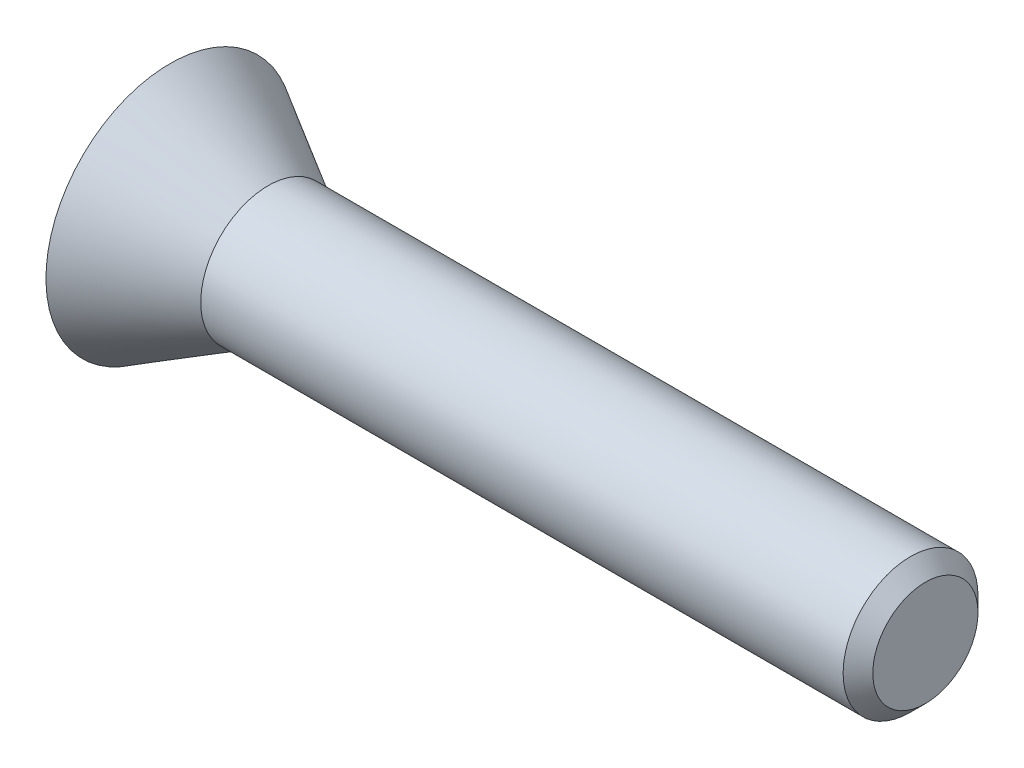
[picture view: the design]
ISO-10303-21;
HEADER;
FILE_DESCRIPTION(('STEP AP214'),'2;1');
FILE_NAME('part.step','',(''),(''),'','','');
FILE_SCHEMA(('AUTOMOTIVE_DESIGN { 1 0 10303 214 1 1 1 1 }'));
ENDSEC;
DATA;
#1=APPLICATION_CONTEXT('core data for automotive mechanical design processes');
#2=APPLICATION_PROTOCOL_DEFINITION('international standard','automotive_design',2000,#1);
#3=PRODUCT_CONTEXT('',#1,'mechanical');
#4=PRODUCT('Part','Part','',(#3));
#5=PRODUCT_RELATED_PRODUCT_CATEGORY('part','',(#4));
#6=PRODUCT_DEFINITION_FORMATION('','',#4);
#7=PRODUCT_DEFINITION_CONTEXT('part definition',#1,'design');
#8=PRODUCT_DEFINITION('design','',#6,#7);
#9=PRODUCT_DEFINITION_SHAPE('','',#8);
#10=(LENGTH_UNIT() NAMED_UNIT(*) SI_UNIT(.MILLI.,.METRE.));
#11=(NAMED_UNIT(*) PLANE_ANGLE_UNIT() SI_UNIT($,.RADIAN.));
#12=(NAMED_UNIT(*) SI_UNIT($,.STERADIAN.) SOLID_ANGLE_UNIT());
#13=UNCERTAINTY_MEASURE_WITH_UNIT(LENGTH_MEASURE(1.E-05),#10,'distance_accuracy_value','');
#14=(GEOMETRIC_REPRESENTATION_CONTEXT(3) GLOBAL_UNCERTAINTY_ASSIGNED_CONTEXT((#13)) GLOBAL_UNIT_ASSIGNED_CONTEXT((#10,
#11,#12)) REPRESENTATION_CONTEXT('',''));
#15=CARTESIAN_POINT('',(0.,0.,0.));
#16=DIRECTION('',(0.,0.,1.));
#17=DIRECTION('',(1.,0.,0.));
#18=AXIS2_PLACEMENT_3D('',#15,#16,#17);
#19=CARTESIAN_POINT('',(-7.,0.,0.));
#20=DIRECTION('',(1.,0.,0.));
#21=DIRECTION('',(0.,0.,-1.));
#22=AXIS2_PLACEMENT_3D('',#19,#20,#21);
#23=PLANE('',#22);
#24=CARTESIAN_POINT('',(-7.,-1.00253926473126,-0.988193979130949));
#25=CARTESIAN_POINT('',(-7.,-1.00211098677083,-0.966842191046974));
#26=CARTESIAN_POINT('',(-7.,-1.00127782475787,-0.92530491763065));
#27=CARTESIAN_POINT('',(-7.,-0.994369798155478,-0.864879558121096));
#28=CARTESIAN_POINT('',(-7.,-0.982370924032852,-0.808239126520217));
#29=CARTESIAN_POINT('',(-7.,-0.965811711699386,-0.755134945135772));
#30=CARTESIAN_POINT('',(-7.,-0.944644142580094,-0.70556513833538));
#31=CARTESIAN_POINT('',(-7.,-0.918692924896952,-0.659749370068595));
#32=CARTESIAN_POINT('',(-7.,-0.887939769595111,-0.617664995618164));
#33=CARTESIAN_POINT('',(-7.,-0.852451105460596,-0.579524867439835));
#34=CARTESIAN_POINT('',(-7.,-0.812669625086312,-0.545597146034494));
#35=CARTESIAN_POINT('',(-7.,-0.768983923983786,-0.515962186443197));
#36=CARTESIAN_POINT('',(-7.,-0.721408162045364,-0.490870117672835));
#37=CARTESIAN_POINT('',(-7.,-0.669918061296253,-0.470519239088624));
#38=CARTESIAN_POINT('',(-7.,-0.614672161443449,-0.454557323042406));
#39=CARTESIAN_POINT('',(-7.,-0.55563240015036,-0.443761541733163));
#40=CARTESIAN_POINT('',(-7.,-0.492762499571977,-0.436490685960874));
#41=CARTESIAN_POINT('',(-7.,-0.449551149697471,-0.435713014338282));
#42=CARTESIAN_POINT('',(-7.,-0.42729575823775,-0.435312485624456));
#43=B_SPLINE_CURVE_WITH_KNOTS('',3,(#24,#25,#26,#27,#28,#29,#30,#31,#32,#33,#34,#35,#36,#37,#38,
#39,#40,#41,#42),.UNSPECIFIED.,.F.,.F.,(4,1,1,1,1,1,1,1,1,1,1,1,1,1,1,1,4),(0.,
0.0706034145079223,0.137350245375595,0.200790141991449,0.261822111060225,0.321037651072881,
0.378713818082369,0.435588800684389,0.493032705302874,0.550614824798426,0.60814515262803,
0.667276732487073,0.728130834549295,0.790952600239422,0.85714223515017,0.926423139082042,1.),.UNSPECIFIED.);
#44=CARTESIAN_POINT('',(-7.,-1.00253926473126,-0.988193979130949));
#45=VERTEX_POINT('',#44);
#46=CARTESIAN_POINT('',(-7.,-0.42729575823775,-0.435312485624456));
#47=VERTEX_POINT('',#46);
#48=EDGE_CURVE('E381',#45,#47,#43,.T.);
#49=ORIENTED_EDGE('',*,*,#48,.F.);
#50=CARTESIAN_POINT('',(-7.,-0.416885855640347,-1.54261768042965));
#51=CARTESIAN_POINT('',(-7.,-0.43939637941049,-1.54220300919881));
#52=CARTESIAN_POINT('',(-7.,-0.483372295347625,-1.54139291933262));
#53=CARTESIAN_POINT('',(-7.,-0.547285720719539,-1.53424727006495));
#54=CARTESIAN_POINT('',(-7.,-0.607446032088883,-1.52329861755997));
#55=CARTESIAN_POINT('',(-7.,-0.663632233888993,-1.50749191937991));
#56=CARTESIAN_POINT('',(-7.,-0.715983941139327,-1.48704519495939));
#57=CARTESIAN_POINT('',(-7.,-0.764518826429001,-1.46192670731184));
#58=CARTESIAN_POINT('',(-7.,-0.808997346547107,-1.43202089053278));
#59=CARTESIAN_POINT('',(-7.,-0.8497419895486,-1.39817826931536));
#60=CARTESIAN_POINT('',(-7.,-0.885595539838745,-1.35976917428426));
#61=CARTESIAN_POINT('',(-7.,-0.917099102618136,-1.3178237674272));
#62=CARTESIAN_POINT('',(-7.,-0.944015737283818,-1.27219444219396));
#63=CARTESIAN_POINT('',(-7.,-0.964954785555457,-1.22220565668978));
#64=CARTESIAN_POINT('',(-7.,-0.982143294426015,-1.16900100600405));
#65=CARTESIAN_POINT('',(-7.,-0.993818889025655,-1.11184817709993));
#66=CARTESIAN_POINT('',(-7.,-1.00140955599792,-1.05124446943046));
#67=CARTESIAN_POINT('',(-7.,-1.0021565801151,-1.00955209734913));
#68=CARTESIAN_POINT('',(-7.,-1.00253926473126,-0.988193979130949));
#69=B_SPLINE_CURVE_WITH_KNOTS('',3,(#50,#51,#52,#53,#54,#55,#56,#57,#58,#59,#60,#61,#62,#63,#64,
#65,#66,#67,#68),.UNSPECIFIED.,.F.,.F.,(4,1,1,1,1,1,1,1,1,1,1,1,1,1,1,1,4),(0.,
0.0736363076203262,0.143853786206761,0.210167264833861,0.273535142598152,0.334525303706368,
0.393774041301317,0.451974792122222,0.509587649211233,0.566708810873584,0.623480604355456,
0.680964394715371,0.739551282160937,0.800463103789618,0.863640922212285,0.930146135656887,1.),.UNSPECIFIED.);
#70=CARTESIAN_POINT('',(-7.,-0.416885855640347,-1.54261768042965));
#71=VERTEX_POINT('',#70);
#72=EDGE_CURVE('E54',#71,#45,#69,.T.);
#73=ORIENTED_EDGE('',*,*,#72,.F.);
#74=DIRECTION('',(0.,-1.,0.));
#75=VECTOR('',#74,1.);
#76=CARTESIAN_POINT('',(-7.,-0.415343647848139,-1.54261768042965));
#77=LINE('',#76,#75);
#78=CARTESIAN_POINT('',(-7.,-0.415343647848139,-1.54261768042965));
#79=VERTEX_POINT('',#78);
#80=EDGE_CURVE('E425',#79,#71,#77,.T.);
#81=ORIENTED_EDGE('',*,*,#80,.F.);
#82=CARTESIAN_POINT('',(-7.,0.157200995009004,-1.04949673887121));
#83=CARTESIAN_POINT('',(-7.,0.156769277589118,-1.06853625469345));
#84=CARTESIAN_POINT('',(-7.,0.155929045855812,-1.10559198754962));
#85=CARTESIAN_POINT('',(-7.,0.149054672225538,-1.159511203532));
#86=CARTESIAN_POINT('',(-7.,0.136872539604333,-1.20990276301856));
#87=CARTESIAN_POINT('',(-7.,0.120880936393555,-1.25740101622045));
#88=CARTESIAN_POINT('',(-7.,0.0995562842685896,-1.30150728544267));
#89=CARTESIAN_POINT('',(-7.,0.0734630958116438,-1.34233095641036));
#90=CARTESIAN_POINT('',(-7.,0.0429140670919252,-1.37996717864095));
#91=CARTESIAN_POINT('',(-7.,0.00754236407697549,-1.41391992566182));
#92=CARTESIAN_POINT('',(-7.,-0.0317498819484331,-1.44450759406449));
#93=CARTESIAN_POINT('',(-7.,-0.075359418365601,-1.47071997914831));
#94=CARTESIAN_POINT('',(-7.,-0.122557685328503,-1.49324615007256));
#95=CARTESIAN_POINT('',(-7.,-0.173816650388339,-1.51119211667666));
#96=CARTESIAN_POINT('',(-7.,-0.22871985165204,-1.52557500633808));
#97=CARTESIAN_POINT('',(-7.,-0.287578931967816,-1.53528663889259));
#98=CARTESIAN_POINT('',(-7.,-0.350171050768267,-1.54170931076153));
#99=CARTESIAN_POINT('',(-7.,-0.393221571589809,-1.54230934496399));
#100=CARTESIAN_POINT('',(-7.,-0.415343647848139,-1.54261768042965));
#101=B_SPLINE_CURVE_WITH_KNOTS('',3,(#82,#83,#84,#85,#86,#87,#88,#89,#90,#91,#92,#93,#94,#95,
#96,#97,#98,#99,#100),.UNSPECIFIED.,.F.,.F.,(4,1,1,1,1,1,1,1,1,1,1,1,1,1,1,1,4),(0.,
0.0665766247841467,0.12957501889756,0.189644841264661,0.247639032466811,0.304530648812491,
0.36051483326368,0.416743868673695,0.473642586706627,0.531631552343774,0.590524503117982,
0.65124161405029,0.714220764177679,0.780176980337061,0.849489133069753,0.922658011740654,1.),.UNSPECIFIED.);
#102=CARTESIAN_POINT('',(-7.,0.157200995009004,-1.04949673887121));
#103=VERTEX_POINT('',#102);
#104=EDGE_CURVE('E417',#103,#79,#101,.T.);
#105=ORIENTED_EDGE('',*,*,#104,.F.);
#106=CARTESIAN_POINT('',(-7.,0.027655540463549,-0.808526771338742));
#107=CARTESIAN_POINT('',(-7.,0.0380307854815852,-0.814367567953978));
#108=CARTESIAN_POINT('',(-7.,0.0583649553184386,-0.825814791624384));
#109=CARTESIAN_POINT('',(-7.,0.0846820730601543,-0.848364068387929));
#110=CARTESIAN_POINT('',(-7.,0.107536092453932,-0.873513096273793));
#111=CARTESIAN_POINT('',(-7.,0.125713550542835,-0.902598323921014));
#112=CARTESIAN_POINT('',(-7.,0.140094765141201,-0.934757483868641));
#113=CARTESIAN_POINT('',(-7.,0.149899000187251,-0.970253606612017));
#114=CARTESIAN_POINT('',(-7.,0.156331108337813,-1.00877990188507));
#115=CARTESIAN_POINT('',(-7.,0.156903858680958,-1.03558866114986));
#116=CARTESIAN_POINT('',(-7.,0.157200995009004,-1.04949673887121));
#117=B_SPLINE_CURVE_WITH_KNOTS('',3,(#106,#107,#108,#109,#110,#111,#112,#113,#114,#115,#116),
.UNSPECIFIED.,.F.,.F.,(4,1,1,1,1,1,1,1,4),(0.,0.123274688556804,0.24160281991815,
0.357777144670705,0.474683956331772,0.595870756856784,0.722082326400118,0.855819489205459,1.),.UNSPECIFIED.);
#118=CARTESIAN_POINT('',(-7.,0.151420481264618,-0.980963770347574));
#119=VERTEX_POINT('',#118);
#120=EDGE_CURVE('E412',#119,#103,#117,.T.);
#121=ORIENTED_EDGE('',*,*,#120,.F.);
#122=DIRECTION('',(0.,-0.900247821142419,0.435377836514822));
#123=VECTOR('',#122,1.);
#124=CARTESIAN_POINT('',(-7.,0.922136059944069,-1.3536972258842));
#125=LINE('',#124,#123);
#126=CARTESIAN_POINT('',(-7.,0.922136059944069,-1.3536972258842));
#127=VERTEX_POINT('',#126);
#128=EDGE_CURVE('E409',#127,#119,#125,.T.);
#129=ORIENTED_EDGE('',*,*,#128,.F.);
#130=DIRECTION('',(0.,0.,-1.));
#131=VECTOR('',#130,1.);
#132=CARTESIAN_POINT('',(-7.,0.922136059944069,-0.950409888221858));
#133=LINE('',#132,#131);
#134=CARTESIAN_POINT('',(-7.,0.922136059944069,-0.950409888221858));
#135=VERTEX_POINT('',#134);
#136=EDGE_CURVE('E406',#135,#127,#133,.T.);
#137=ORIENTED_EDGE('',*,*,#136,.F.);
#138=DIRECTION('',(0.,0.905627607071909,-0.424073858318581));
#139=VECTOR('',#138,1.);
#140=CARTESIAN_POINT('',(-7.,0.102067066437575,-0.566400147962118));
#141=LINE('',#140,#139);
#142=CARTESIAN_POINT('',(-7.,0.102067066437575,-0.566400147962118));
#143=VERTEX_POINT('',#142);
#144=EDGE_CURVE('E400',#143,#135,#141,.T.);
#145=ORIENTED_EDGE('',*,*,#144,.F.);
#146=CARTESIAN_POINT('',(-7.,-0.426139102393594,-0.435312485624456));
#147=CARTESIAN_POINT('',(-7.,-0.405302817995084,-0.435798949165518));
#148=CARTESIAN_POINT('',(-7.,-0.362890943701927,-0.436789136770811));
#149=CARTESIAN_POINT('',(-7.,-0.298519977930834,-0.443695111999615));
#150=CARTESIAN_POINT('',(-7.,-0.232427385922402,-0.454365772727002));
#151=CARTESIAN_POINT('',(-7.,-0.165204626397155,-0.470017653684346));
#152=CARTESIAN_POINT('',(-7.,-0.0975398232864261,-0.489102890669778));
#153=CARTESIAN_POINT('',(-7.,-0.0302120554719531,-0.511711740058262));
#154=CARTESIAN_POINT('',(-7.,0.036620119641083,-0.536851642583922));
#155=CARTESIAN_POINT('',(-7.,0.0801904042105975,-0.556523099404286));
#156=CARTESIAN_POINT('',(-7.,0.102067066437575,-0.566400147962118));
#157=B_SPLINE_CURVE_WITH_KNOTS('',3,(#146,#147,#148,#149,#150,#151,#152,#153,#154,#155,#156),
.UNSPECIFIED.,.F.,.F.,(4,1,1,1,1,1,1,1,4),(0.,0.114002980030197,0.232050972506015,
0.353906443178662,0.480147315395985,0.609491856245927,0.738474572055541,0.868687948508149,1.),.UNSPECIFIED.);
#158=CARTESIAN_POINT('',(-7.,-0.426139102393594,-0.435312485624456));
#159=VERTEX_POINT('',#158);
#160=EDGE_CURVE('E395',#159,#143,#157,.T.);
#161=ORIENTED_EDGE('',*,*,#160,.F.);
#162=DIRECTION('',(0.,1.,0.));
#163=VECTOR('',#162,1.);
#164=CARTESIAN_POINT('',(-7.,-0.42729575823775,-0.435312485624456));
#165=LINE('',#164,#163);
#166=EDGE_CURVE('E389',#47,#159,#165,.T.);
#167=ORIENTED_EDGE('',*,*,#166,.F.);
#168=EDGE_LOOP('',(#49,#73,#81,#105,#121,#129,#137,#145,#161,#167));
#169=FACE_BOUND('',#168,.T.);
#170=CARTESIAN_POINT('',(-7.,0.,0.));
#171=DIRECTION('',(-1.,0.,0.));
#172=DIRECTION('',(0.,-1.,0.));
#173=AXIS2_PLACEMENT_3D('',#170,#171,#172);
#174=CIRCLE('',#173,2.3);
#175=CARTESIAN_POINT('',(-7.,-2.3,0.));
#176=VERTEX_POINT('',#175);
#177=EDGE_CURVE('E557',#176,#176,#174,.T.);
#178=ORIENTED_EDGE('',*,*,#177,.T.);
#179=EDGE_LOOP('',(#178));
#180=FACE_BOUND('',#179,.T.);
#181=DIRECTION('',(0.,1.,0.));
#182=VECTOR('',#181,1.);
#183=CARTESIAN_POINT('',(-7.,1.01,0.23));
#184=LINE('',#183,#182);
#185=CARTESIAN_POINT('',(-7.,-1.52,0.23));
#186=VERTEX_POINT('',#185);
#187=CARTESIAN_POINT('',(-7.,1.01,0.23));
#188=VERTEX_POINT('',#187);
#189=EDGE_CURVE('E563',#186,#188,#184,.T.);
#190=ORIENTED_EDGE('',*,*,#189,.F.);
#191=CARTESIAN_POINT('',(-7.,-1.52,0.));
#192=DIRECTION('',(-1.,0.,0.));
#193=DIRECTION('',(0.,0.,1.));
#194=AXIS2_PLACEMENT_3D('',#191,#192,#193);
#195=CIRCLE('',#194,0.23);
#196=CARTESIAN_POINT('',(-7.,-1.52,-0.23));
#197=VERTEX_POINT('',#196);
#198=EDGE_CURVE('E652',#197,#186,#195,.T.);
#199=ORIENTED_EDGE('',*,*,#198,.F.);
#200=DIRECTION('',(0.,-1.,0.));
#201=VECTOR('',#200,1.);
#202=CARTESIAN_POINT('',(-7.,1.01,-0.23));
#203=LINE('',#202,#201);
#204=CARTESIAN_POINT('',(-7.,1.01,-0.23));
#205=VERTEX_POINT('',#204);
#206=EDGE_CURVE('E690',#205,#197,#203,.T.);
#207=ORIENTED_EDGE('',*,*,#206,.F.);
#208=DIRECTION('',(0.,0.,1.));
#209=VECTOR('',#208,1.);
#210=CARTESIAN_POINT('',(-7.,1.01,-0.55));
#211=LINE('',#210,#209);
#212=CARTESIAN_POINT('',(-7.,1.01,-0.55));
#213=VERTEX_POINT('',#212);
#214=EDGE_CURVE('E720',#213,#205,#211,.T.);
#215=ORIENTED_EDGE('',*,*,#214,.F.);
#216=DIRECTION('',(0.,-0.858315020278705,-0.513123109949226));
#217=VECTOR('',#216,1.);
#218=CARTESIAN_POINT('',(-7.,1.93,0.));
#219=LINE('',#218,#217);
#220=CARTESIAN_POINT('',(-7.,1.93,0.));
#221=VERTEX_POINT('',#220);
#222=EDGE_CURVE('E717',#221,#213,#219,.T.);
#223=ORIENTED_EDGE('',*,*,#222,.F.);
#224=DIRECTION('',(0.,0.858315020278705,-0.513123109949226));
#225=VECTOR('',#224,1.);
#226=CARTESIAN_POINT('',(-7.,1.93,0.));
#227=LINE('',#226,#225);
#228=CARTESIAN_POINT('',(-7.,1.01,0.55));
#229=VERTEX_POINT('',#228);
#230=EDGE_CURVE('E714',#229,#221,#227,.T.);
#231=ORIENTED_EDGE('',*,*,#230,.F.);
#232=DIRECTION('',(0.,0.,1.));
#233=VECTOR('',#232,1.);
#234=CARTESIAN_POINT('',(-7.,1.01,0.55));
#235=LINE('',#234,#233);
#236=EDGE_CURVE('E711',#188,#229,#235,.T.);
#237=ORIENTED_EDGE('',*,*,#236,.F.);
#238=EDGE_LOOP('',(#190,#199,#207,#215,#223,#231,#237));
#239=FACE_BOUND('',#238,.T.);
#240=DIRECTION('',(0.,1.,0.));
#241=VECTOR('',#240,1.);
#242=CARTESIAN_POINT('',(-7.,-0.977863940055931,1.5996152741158));
#243=LINE('',#242,#241);
#244=CARTESIAN_POINT('',(-7.,-0.977863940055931,1.5996152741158));
#245=VERTEX_POINT('',#244);
#246=CARTESIAN_POINT('',(-7.,-0.654771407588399,1.5996152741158));
#247=VERTEX_POINT('',#246);
#248=EDGE_CURVE('E568',#245,#247,#243,.T.);
#249=ORIENTED_EDGE('',*,*,#248,.F.);
#250=DIRECTION('',(0.,0.,1.));
#251=VECTOR('',#250,1.);
#252=CARTESIAN_POINT('',(-7.,-0.977863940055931,0.480743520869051));
#253=LINE('',#252,#251);
#254=CARTESIAN_POINT('',(-7.,-0.977863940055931,0.480743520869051));
#255=VERTEX_POINT('',#254);
#256=EDGE_CURVE('E434',#255,#245,#253,.T.);
#257=ORIENTED_EDGE('',*,*,#256,.F.);
#258=DIRECTION('',(0.,-1.,0.));
#259=VECTOR('',#258,1.);
#260=CARTESIAN_POINT('',(-7.,-0.632409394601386,0.480743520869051));
#261=LINE('',#260,#259);
#262=CARTESIAN_POINT('',(-7.,-0.632409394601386,0.480743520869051));
#263=VERTEX_POINT('',#262);
#264=EDGE_CURVE('E456',#263,#255,#261,.T.);
#265=ORIENTED_EDGE('',*,*,#264,.F.);
#266=DIRECTION('',(0.,0.,-1.));
#267=VECTOR('',#266,1.);
#268=CARTESIAN_POINT('',(-7.,-0.632409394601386,1.12731413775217));
#269=LINE('',#268,#267);
#270=CARTESIAN_POINT('',(-7.,-0.632409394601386,1.12731413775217));
#271=VERTEX_POINT('',#270);
#272=EDGE_CURVE('E645',#271,#263,#269,.T.);
#273=ORIENTED_EDGE('',*,*,#272,.F.);
#274=DIRECTION('',(0.,-0.786034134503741,0.618183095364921));
#275=VECTOR('',#274,1.);
#276=CARTESIAN_POINT('',(-7.,-0.0402016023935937,0.661567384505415));
#277=LINE('',#276,#275);
#278=CARTESIAN_POINT('',(-7.,-0.0402016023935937,0.661567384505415));
#279=VERTEX_POINT('',#278);
#280=EDGE_CURVE('E639',#279,#271,#277,.T.);
#281=ORIENTED_EDGE('',*,*,#280,.F.);
#282=CARTESIAN_POINT('',(-7.,0.448678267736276,0.491153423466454));
#283=CARTESIAN_POINT('',(-7.,0.427059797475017,0.491644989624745));
#284=CARTESIAN_POINT('',(-7.,0.383784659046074,0.492628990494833));
#285=CARTESIAN_POINT('',(-7.,0.319017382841,0.501511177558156));
#286=CARTESIAN_POINT('',(-7.,0.254580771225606,0.515824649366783));
#287=CARTESIAN_POINT('',(-7.,0.190786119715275,0.535482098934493));
#288=CARTESIAN_POINT('',(-7.,0.128738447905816,0.559901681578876));
#289=CARTESIAN_POINT('',(-7.,0.0692875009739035,0.589209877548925));
#290=CARTESIAN_POINT('',(-7.,0.0124069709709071,0.622287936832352));
#291=CARTESIAN_POINT('',(-7.,-0.0226989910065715,0.648499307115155));
#292=CARTESIAN_POINT('',(-7.,-0.0402016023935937,0.661567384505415));
#293=B_SPLINE_CURVE_WITH_KNOTS('',3,(#282,#283,#284,#285,#286,#287,#288,#289,#290,#291,#292),
.UNSPECIFIED.,.F.,.F.,(4,1,1,1,1,1,1,1,4),(0.,0.123046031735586,0.246309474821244,
0.371480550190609,0.498560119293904,0.626024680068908,0.750715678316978,0.875715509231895,1.),.UNSPECIFIED.);
#294=CARTESIAN_POINT('',(-7.,0.448678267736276,0.491153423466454));
#295=VERTEX_POINT('',#294);
#296=EDGE_CURVE('E634',#295,#279,#293,.T.);
#297=ORIENTED_EDGE('',*,*,#296,.F.);
#298=DIRECTION('',(0.,-1.,0.));
#299=VECTOR('',#298,1.);
#300=CARTESIAN_POINT('',(-7.,0.450220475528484,0.491153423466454));
#301=LINE('',#300,#299);
#302=CARTESIAN_POINT('',(-7.,0.450220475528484,0.491153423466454));
#303=VERTEX_POINT('',#302);
#304=EDGE_CURVE('E628',#303,#295,#301,.T.);
#305=ORIENTED_EDGE('',*,*,#304,.F.);
#306=CARTESIAN_POINT('',(-7.,0.946811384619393,1.05058930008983));
#307=CARTESIAN_POINT('',(-7.,0.946504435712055,1.02898096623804));
#308=CARTESIAN_POINT('',(-7.,0.945907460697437,0.986955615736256));
#309=CARTESIAN_POINT('',(-7.,0.939463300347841,0.925773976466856));
#310=CARTESIAN_POINT('',(-7.,0.929737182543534,0.868208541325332));
#311=CARTESIAN_POINT('',(-7.,0.915508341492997,0.814351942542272));
#312=CARTESIAN_POINT('',(-7.,0.896948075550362,0.764420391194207));
#313=CARTESIAN_POINT('',(-7.,0.874568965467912,0.718264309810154));
#314=CARTESIAN_POINT('',(-7.,0.848180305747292,0.67578721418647));
#315=CARTESIAN_POINT('',(-7.,0.817725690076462,0.637314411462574));
#316=CARTESIAN_POINT('',(-7.,0.783758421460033,0.602698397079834));
#317=CARTESIAN_POINT('',(-7.,0.745933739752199,0.572903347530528));
#318=CARTESIAN_POINT('',(-7.,0.705016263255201,0.547110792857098));
#319=CARTESIAN_POINT('',(-7.,0.660212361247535,0.526948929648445));
#320=CARTESIAN_POINT('',(-7.,0.612575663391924,0.51035006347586));
#321=CARTESIAN_POINT('',(-7.,0.561252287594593,0.499602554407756));
#322=CARTESIAN_POINT('',(-7.,0.506846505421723,0.492360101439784));
#323=CARTESIAN_POINT('',(-7.,0.469394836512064,0.491562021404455));
#324=CARTESIAN_POINT('',(-7.,0.450220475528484,0.491153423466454));
#325=B_SPLINE_CURVE_WITH_KNOTS('',3,(#306,#307,#308,#309,#310,#311,#312,#313,#314,#315,#316,
#317,#318,#319,#320,#321,#322,#323,#324),.UNSPECIFIED.,.F.,.F.,(4,1,1,1,1,1,1,1,1,1,1,1,1,1,1,1,
4),(0.,0.0762312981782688,0.148259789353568,0.216860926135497,0.28210063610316,
0.344528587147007,0.404571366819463,0.462840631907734,0.520642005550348,0.577409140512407,
0.633580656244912,0.690215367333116,0.747647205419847,0.806597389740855,0.867894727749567,
0.932365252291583,1.),.UNSPECIFIED.);
#326=CARTESIAN_POINT('',(-7.,0.946811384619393,1.05058930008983));
#327=VERTEX_POINT('',#326);
#328=EDGE_CURVE('E620',#327,#303,#325,.T.);
#329=ORIENTED_EDGE('',*,*,#328,.F.);
#330=CARTESIAN_POINT('',(-7.,0.376580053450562,1.62313394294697));
#331=CARTESIAN_POINT('',(-7.,0.398603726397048,1.62133041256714));
#332=CARTESIAN_POINT('',(-7.,0.441593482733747,1.61780995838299));
#333=CARTESIAN_POINT('',(-7.,0.503780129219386,1.60626838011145));
#334=CARTESIAN_POINT('',(-7.,0.562355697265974,1.59135134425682));
#335=CARTESIAN_POINT('',(-7.,0.617308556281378,1.57237486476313));
#336=CARTESIAN_POINT('',(-7.,0.668002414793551,1.54799002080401));
#337=CARTESIAN_POINT('',(-7.,0.715497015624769,1.52059290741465));
#338=CARTESIAN_POINT('',(-7.,0.758323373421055,1.48764104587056));
#339=CARTESIAN_POINT('',(-7.,0.797914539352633,1.45157061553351));
#340=CARTESIAN_POINT('',(-7.,0.832785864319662,1.41139460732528));
#341=CARTESIAN_POINT('',(-7.,0.863547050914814,1.36855594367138));
#342=CARTESIAN_POINT('',(-7.,0.889145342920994,1.3224068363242));
#343=CARTESIAN_POINT('',(-7.,0.910380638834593,1.273648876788));
#344=CARTESIAN_POINT('',(-7.,0.926497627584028,1.22174147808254));
#345=CARTESIAN_POINT('',(-7.,0.938570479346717,1.1673626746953));
#346=CARTESIAN_POINT('',(-7.,0.945532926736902,1.10988829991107));
#347=CARTESIAN_POINT('',(-7.,0.94637874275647,1.07065662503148));
#348=CARTESIAN_POINT('',(-7.,0.946811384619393,1.05058930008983));
#349=B_SPLINE_CURVE_WITH_KNOTS('',3,(#330,#331,#332,#333,#334,#335,#336,#337,#338,#339,#340,
#341,#342,#343,#344,#345,#346,#347,#348),.UNSPECIFIED.,.F.,.F.,(4,1,1,1,1,1,1,1,1,1,1,1,1,1,1,1,
4),(0.,0.0733268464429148,0.14313249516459,0.209679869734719,0.273918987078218,0.33576228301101,
0.396210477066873,0.45560885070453,0.514796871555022,0.573764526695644,0.631900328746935,
0.689592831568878,0.748648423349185,0.808163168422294,0.86976604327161,0.933384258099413,1.),.UNSPECIFIED.);
#350=CARTESIAN_POINT('',(-7.,0.376580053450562,1.62313394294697));
#351=VERTEX_POINT('',#350);
#352=EDGE_CURVE('E615',#351,#327,#349,.T.);
#353=ORIENTED_EDGE('',*,*,#352,.F.);
#354=DIRECTION('',(0.,1.,0.));
#355=VECTOR('',#354,1.);
#356=CARTESIAN_POINT('',(-7.,0.375423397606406,1.62313394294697));
#357=LINE('',#356,#355);
#358=CARTESIAN_POINT('',(-7.,0.375423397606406,1.62313394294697));
#359=VERTEX_POINT('',#358);
#360=EDGE_CURVE('E612',#359,#351,#357,.T.);
#361=ORIENTED_EDGE('',*,*,#360,.F.);
#362=DIRECTION('',(0.,0.,1.));
#363=VECTOR('',#362,1.);
#364=CARTESIAN_POINT('',(-7.,0.375423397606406,1.25763069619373));
#365=LINE('',#364,#363);
#366=CARTESIAN_POINT('',(-7.,0.375423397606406,1.25763069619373));
#367=VERTEX_POINT('',#366);
#368=EDGE_CURVE('E609',#367,#359,#365,.T.);
#369=ORIENTED_EDGE('',*,*,#368,.F.);
#370=DIRECTION('',(0.,-1.,0.));
#371=VECTOR('',#370,1.);
#372=CARTESIAN_POINT('',(-7.,0.376580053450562,1.25763069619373));
#373=LINE('',#372,#371);
#374=CARTESIAN_POINT('',(-7.,0.376580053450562,1.25763069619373));
#375=VERTEX_POINT('',#374);
#376=EDGE_CURVE('E603',#375,#367,#373,.T.);
#377=ORIENTED_EDGE('',*,*,#376,.F.);
#378=CARTESIAN_POINT('',(-7.,0.601356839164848,1.04789043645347));
#379=CARTESIAN_POINT('',(-7.,0.600811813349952,1.06185822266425));
#380=CARTESIAN_POINT('',(-7.,0.599752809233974,1.08899811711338));
#381=CARTESIAN_POINT('',(-7.,0.588016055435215,1.12741926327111));
#382=CARTESIAN_POINT('',(-7.,0.569606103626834,1.16204046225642));
#383=CARTESIAN_POINT('',(-7.,0.543337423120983,1.19188668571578));
#384=CARTESIAN_POINT('',(-7.,0.510356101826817,1.21660161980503));
#385=CARTESIAN_POINT('',(-7.,0.471517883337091,1.23666018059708));
#386=CARTESIAN_POINT('',(-7.,0.426121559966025,1.25028380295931));
#387=CARTESIAN_POINT('',(-7.,0.393625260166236,1.25510293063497));
#388=CARTESIAN_POINT('',(-7.,0.376580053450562,1.25763069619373));
#389=B_SPLINE_CURVE_WITH_KNOTS('',3,(#378,#379,#380,#381,#382,#383,#384,#385,#386,#387,#388),
.UNSPECIFIED.,.F.,.F.,(4,1,1,1,1,1,1,1,4),(0.,0.122603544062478,0.238222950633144,
0.350089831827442,0.465559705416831,0.58502806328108,0.711014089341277,0.848418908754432,1.),.UNSPECIFIED.);
#390=CARTESIAN_POINT('',(-7.,0.601356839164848,1.04789043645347));
#391=VERTEX_POINT('',#390);
#392=EDGE_CURVE('E595',#391,#375,#389,.T.);
#393=ORIENTED_EDGE('',*,*,#392,.F.);
#394=CARTESIAN_POINT('',(-7.,0.440196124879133,0.858198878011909));
#395=CARTESIAN_POINT('',(-7.,0.452344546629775,0.858725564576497));
#396=CARTESIAN_POINT('',(-7.,0.475618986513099,0.859734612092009));
#397=CARTESIAN_POINT('',(-7.,0.508413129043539,0.869241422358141));
#398=CARTESIAN_POINT('',(-7.,0.536971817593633,0.884822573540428));
#399=CARTESIAN_POINT('',(-7.,0.560561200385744,0.907138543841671));
#400=CARTESIAN_POINT('',(-7.,0.579218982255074,0.934920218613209));
#401=CARTESIAN_POINT('',(-7.,0.592367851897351,0.968161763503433));
#402=CARTESIAN_POINT('',(-7.,0.59990788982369,1.00642824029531));
#403=CARTESIAN_POINT('',(-7.,0.600857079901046,1.03358964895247));
#404=CARTESIAN_POINT('',(-7.,0.601356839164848,1.04789043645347));
#405=B_SPLINE_CURVE_WITH_KNOTS('',3,(#394,#395,#396,#397,#398,#399,#400,#401,#402,#403,#404),
.UNSPECIFIED.,.F.,.F.,(4,1,1,1,1,1,1,1,4),(0.,0.128749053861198,0.246662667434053,
0.359069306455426,0.471077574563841,0.588039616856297,0.711712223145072,0.848213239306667,1.),.UNSPECIFIED.);
#406=CARTESIAN_POINT('',(-7.,0.440196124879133,0.858198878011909));
#407=VERTEX_POINT('',#406);
#408=EDGE_CURVE('E590',#407,#391,#405,.T.);
#409=ORIENTED_EDGE('',*,*,#408,.F.);
#410=DIRECTION('',(0.,1.,0.));
#411=VECTOR('',#410,1.);
#412=CARTESIAN_POINT('',(-7.,0.43749726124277,0.858198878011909));
#413=LINE('',#412,#411);
#414=CARTESIAN_POINT('',(-7.,0.43749726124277,0.858198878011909));
#415=VERTEX_POINT('',#414);
#416=EDGE_CURVE('E584',#415,#407,#413,.T.);
#417=ORIENTED_EDGE('',*,*,#416,.F.);
#418=CARTESIAN_POINT('',(-7.,0.205394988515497,0.950345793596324));
#419=CARTESIAN_POINT('',(-7.,0.224556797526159,0.93674672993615));
#420=CARTESIAN_POINT('',(-7.,0.261893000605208,0.910249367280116));
#421=CARTESIAN_POINT('',(-7.,0.313166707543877,0.88626721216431));
#422=CARTESIAN_POINT('',(-7.,0.353365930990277,0.87132732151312));
#423=CARTESIAN_POINT('',(-7.,0.382518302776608,0.86420729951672));
#424=CARTESIAN_POINT('',(-7.,0.410332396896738,0.859128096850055));
#425=CARTESIAN_POINT('',(-7.,0.42860852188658,0.858502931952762));
#426=CARTESIAN_POINT('',(-7.,0.43749726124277,0.858198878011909));
#427=B_SPLINE_CURVE_WITH_KNOTS('',3,(#418,#419,#420,#421,#422,#423,#424,#425,#426),
.UNSPECIFIED.,.F.,.F.,(4,1,1,1,1,1,4),(0.,0.27737542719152,0.540457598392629,0.666416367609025,
0.784009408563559,0.894951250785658,1.),.UNSPECIFIED.);
#428=CARTESIAN_POINT('',(-7.,0.205394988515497,0.950345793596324));
#429=VERTEX_POINT('',#428);
#430=EDGE_CURVE('E575',#429,#415,#427,.T.);
#431=ORIENTED_EDGE('',*,*,#430,.F.);
#432=DIRECTION('',(0.,0.798150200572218,-0.602458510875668));
#433=VECTOR('',#432,1.);
#434=CARTESIAN_POINT('',(-7.,-0.654771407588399,1.5996152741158));
#435=LINE('',#434,#433);
#436=EDGE_CURVE('E572',#247,#429,#435,.T.);
#437=ORIENTED_EDGE('',*,*,#436,.F.);
#438=EDGE_LOOP('',(#249,#257,#265,#273,#281,#297,#305,#329,#353,#361,#369,#377,#393,#409,#417,
#431,#437));
#439=FACE_BOUND('',#438,.T.);
#440=ADVANCED_FACE('F39',(#169,#180,#239,#439),#23,.F.);
#441=CARTESIAN_POINT('',(-7.,0.,0.));
#442=DIRECTION('',(-1.,0.,0.));
#443=DIRECTION('',(0.,-1.,0.));
#444=AXIS2_PLACEMENT_3D('',#441,#442,#443);
#445=CONICAL_SURFACE('',#444,2.3,0.523598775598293);
#446=CARTESIAN_POINT('',(-5.18134665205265,0.,0.));
#447=DIRECTION('',(-1.,0.,0.));
#448=DIRECTION('',(0.,-1.,0.));
#449=AXIS2_PLACEMENT_3D('',#446,#447,#448);
#450=CIRCLE('',#449,1.25);
#451=CARTESIAN_POINT('',(-5.18134665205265,-1.25,0.));
#452=VERTEX_POINT('',#451);
#453=EDGE_CURVE('E727',#452,#452,#450,.T.);
#454=ORIENTED_EDGE('',*,*,#453,.T.);
#455=EDGE_LOOP('',(#454));
#456=FACE_BOUND('',#455,.T.);
#457=ORIENTED_EDGE('',*,*,#177,.F.);
#458=EDGE_LOOP('',(#457));
#459=FACE_BOUND('',#458,.T.);
#460=ADVANCED_FACE('F530',(#456,#459),#445,.T.);
#461=CARTESIAN_POINT('',(-7.,0.,0.));
#462=DIRECTION('',(-1.,0.,0.));
#463=DIRECTION('',(0.,-1.,0.));
#464=AXIS2_PLACEMENT_3D('',#461,#462,#463);
#465=CYLINDRICAL_SURFACE('',#464,1.25);
#466=CARTESIAN_POINT('',(6.725,0.,0.));
#467=DIRECTION('',(1.,0.,0.));
#468=DIRECTION('',(0.,1.,0.));
#469=AXIS2_PLACEMENT_3D('',#466,#467,#468);
#470=CIRCLE('',#469,1.25);
#471=CARTESIAN_POINT('',(6.725,1.25,0.));
#472=VERTEX_POINT('',#471);
#473=EDGE_CURVE('E47',#472,#472,#470,.F.);
#474=ORIENTED_EDGE('',*,*,#473,.T.);
#475=EDGE_LOOP('',(#474));
#476=FACE_BOUND('',#475,.T.);
#477=ORIENTED_EDGE('',*,*,#453,.F.);
#478=EDGE_LOOP('',(#477));
#479=FACE_BOUND('',#478,.T.);
#480=ADVANCED_FACE('F527',(#476,#479),#465,.T.);
#481=CARTESIAN_POINT('',(7.,0.,0.));
#482=DIRECTION('',(1.,0.,0.));
#483=DIRECTION('',(0.,0.,-1.));
#484=AXIS2_PLACEMENT_3D('',#481,#482,#483);
#485=PLANE('',#484);
#486=CARTESIAN_POINT('',(7.,0.,0.));
#487=DIRECTION('',(1.,0.,0.));
#488=DIRECTION('',(0.,0.,-1.));
#489=AXIS2_PLACEMENT_3D('',#486,#487,#488);
#490=CIRCLE('',#489,0.975000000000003);
#491=CARTESIAN_POINT('',(7.,0.,-0.975000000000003));
#492=VERTEX_POINT('',#491);
#493=EDGE_CURVE('E11',#492,#492,#490,.T.);
#494=ORIENTED_EDGE('',*,*,#493,.T.);
#495=EDGE_LOOP('',(#494));
#496=FACE_BOUND('',#495,.T.);
#497=ADVANCED_FACE('F525',(#496),#485,.T.);
#498=CARTESIAN_POINT('',(-6.4,-1.52,0.));
#499=DIRECTION('',(-1.,0.,0.));
#500=DIRECTION('',(0.,0.,1.));
#501=AXIS2_PLACEMENT_3D('',#498,#499,#500);
#502=CYLINDRICAL_SURFACE('',#501,0.23);
#503=ORIENTED_EDGE('',*,*,#198,.T.);
#504=DIRECTION('',(-1.,0.,0.));
#505=VECTOR('',#504,1.);
#506=CARTESIAN_POINT('',(-6.4,-1.52,0.23));
#507=LINE('',#506,#505);
#508=CARTESIAN_POINT('',(-6.4,-1.52,0.23));
#509=VERTEX_POINT('',#508);
#510=EDGE_CURVE('E708',#509,#186,#507,.T.);
#511=ORIENTED_EDGE('',*,*,#510,.F.);
#512=CARTESIAN_POINT('',(-6.4,-1.52,0.));
#513=DIRECTION('',(-1.,0.,0.));
#514=DIRECTION('',(0.,0.,1.));
#515=AXIS2_PLACEMENT_3D('',#512,#513,#514);
#516=CIRCLE('',#515,0.23);
#517=CARTESIAN_POINT('',(-6.4,-1.52,-0.23));
#518=VERTEX_POINT('',#517);
#519=EDGE_CURVE('E686',#518,#509,#516,.T.);
#520=ORIENTED_EDGE('',*,*,#519,.F.);
#521=DIRECTION('',(-1.,0.,0.));
#522=VECTOR('',#521,1.);
#523=CARTESIAN_POINT('',(-6.4,-1.52,-0.23));
#524=LINE('',#523,#522);
#525=EDGE_CURVE('E725',#518,#197,#524,.T.);
#526=ORIENTED_EDGE('',*,*,#525,.T.);
#527=EDGE_LOOP('',(#503,#511,#520,#526));
#528=FACE_BOUND('',#527,.T.);
#529=ADVANCED_FACE('F503',(#528),#502,.F.);
#530=CARTESIAN_POINT('',(-6.4,1.01,-0.23));
#531=DIRECTION('',(0.,0.,-1.));
#532=DIRECTION('',(0.,1.,0.));
#533=AXIS2_PLACEMENT_3D('',#530,#531,#532);
#534=PLANE('',#533);
#535=ORIENTED_EDGE('',*,*,#206,.T.);
#536=ORIENTED_EDGE('',*,*,#525,.F.);
#537=DIRECTION('',(0.,-1.,0.));
#538=VECTOR('',#537,1.);
#539=CARTESIAN_POINT('',(-6.4,1.01,-0.23));
#540=LINE('',#539,#538);
#541=CARTESIAN_POINT('',(-6.4,1.01,-0.23));
#542=VERTEX_POINT('',#541);
#543=EDGE_CURVE('E705',#542,#518,#540,.T.);
#544=ORIENTED_EDGE('',*,*,#543,.F.);
#545=DIRECTION('',(-1.,0.,0.));
#546=VECTOR('',#545,1.);
#547=CARTESIAN_POINT('',(-6.4,1.01,-0.23));
#548=LINE('',#547,#546);
#549=EDGE_CURVE('E728',#542,#205,#548,.T.);
#550=ORIENTED_EDGE('',*,*,#549,.T.);
#551=EDGE_LOOP('',(#535,#536,#544,#550));
#552=FACE_BOUND('',#551,.T.);
#553=ADVANCED_FACE('F499',(#552),#534,.F.);
#554=CARTESIAN_POINT('',(-6.4,1.01,-0.55));
#555=DIRECTION('',(0.,-1.,0.));
#556=DIRECTION('',(0.,0.,-1.));
#557=AXIS2_PLACEMENT_3D('',#554,#555,#556);
#558=PLANE('',#557);
#559=ORIENTED_EDGE('',*,*,#214,.T.);
#560=ORIENTED_EDGE('',*,*,#549,.F.);
#561=DIRECTION('',(0.,0.,1.));
#562=VECTOR('',#561,1.);
#563=CARTESIAN_POINT('',(-6.4,1.01,-0.55));
#564=LINE('',#563,#562);
#565=CARTESIAN_POINT('',(-6.4,1.01,-0.55));
#566=VERTEX_POINT('',#565);
#567=EDGE_CURVE('E702',#566,#542,#564,.T.);
#568=ORIENTED_EDGE('',*,*,#567,.F.);
#569=DIRECTION('',(-1.,0.,0.));
#570=VECTOR('',#569,1.);
#571=CARTESIAN_POINT('',(-6.4,1.01,-0.55));
#572=LINE('',#571,#570);
#573=EDGE_CURVE('E730',#566,#213,#572,.T.);
#574=ORIENTED_EDGE('',*,*,#573,.T.);
#575=EDGE_LOOP('',(#559,#560,#568,#574));
#576=FACE_BOUND('',#575,.T.);
#577=ADVANCED_FACE('F502',(#576),#558,.F.);
#578=CARTESIAN_POINT('',(-6.4,1.93,0.));
#579=DIRECTION('',(0.,0.513123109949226,-0.858315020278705));
#580=DIRECTION('',(0.,0.858315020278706,0.513123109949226));
#581=AXIS2_PLACEMENT_3D('',#578,#579,#580);
#582=PLANE('',#581);
#583=ORIENTED_EDGE('',*,*,#222,.T.);
#584=ORIENTED_EDGE('',*,*,#573,.F.);
#585=DIRECTION('',(0.,-0.858315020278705,-0.513123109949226));
#586=VECTOR('',#585,1.);
#587=CARTESIAN_POINT('',(-6.4,1.93,0.));
#588=LINE('',#587,#586);
#589=CARTESIAN_POINT('',(-6.4,1.93,0.));
#590=VERTEX_POINT('',#589);
#591=EDGE_CURVE('E699',#590,#566,#588,.T.);
#592=ORIENTED_EDGE('',*,*,#591,.F.);
#593=DIRECTION('',(-1.,0.,0.));
#594=VECTOR('',#593,1.);
#595=CARTESIAN_POINT('',(-6.4,1.93,0.));
#596=LINE('',#595,#594);
#597=EDGE_CURVE('E732',#590,#221,#596,.T.);
#598=ORIENTED_EDGE('',*,*,#597,.T.);
#599=EDGE_LOOP('',(#583,#584,#592,#598));
#600=FACE_BOUND('',#599,.T.);
#601=ADVANCED_FACE('F507',(#600),#582,.F.);
#602=CARTESIAN_POINT('',(-6.4,1.93,0.));
#603=DIRECTION('',(0.,0.513123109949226,0.858315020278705));
#604=DIRECTION('',(0.,-0.858315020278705,0.513123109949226));
#605=AXIS2_PLACEMENT_3D('',#602,#603,#604);
#606=PLANE('',#605);
#607=ORIENTED_EDGE('',*,*,#230,.T.);
#608=ORIENTED_EDGE('',*,*,#597,.F.);
#609=DIRECTION('',(0.,0.858315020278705,-0.513123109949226));
#610=VECTOR('',#609,1.);
#611=CARTESIAN_POINT('',(-6.4,1.93,0.));
#612=LINE('',#611,#610);
#613=CARTESIAN_POINT('',(-6.4,1.01,0.55));
#614=VERTEX_POINT('',#613);
#615=EDGE_CURVE('E696',#614,#590,#612,.T.);
#616=ORIENTED_EDGE('',*,*,#615,.F.);
#617=DIRECTION('',(-1.,0.,0.));
#618=VECTOR('',#617,1.);
#619=CARTESIAN_POINT('',(-6.4,1.01,0.55));
#620=LINE('',#619,#618);
#621=EDGE_CURVE('E734',#614,#229,#620,.T.);
#622=ORIENTED_EDGE('',*,*,#621,.T.);
#623=EDGE_LOOP('',(#607,#608,#616,#622));
#624=FACE_BOUND('',#623,.T.);
#625=ADVANCED_FACE('F511',(#624),#606,.F.);
#626=CARTESIAN_POINT('',(-6.4,1.01,0.55));
#627=DIRECTION('',(0.,-1.,0.));
#628=DIRECTION('',(0.,0.,-1.));
#629=AXIS2_PLACEMENT_3D('',#626,#627,#628);
#630=PLANE('',#629);
#631=ORIENTED_EDGE('',*,*,#236,.T.);
#632=ORIENTED_EDGE('',*,*,#621,.F.);
#633=DIRECTION('',(0.,0.,1.));
#634=VECTOR('',#633,1.);
#635=CARTESIAN_POINT('',(-6.4,1.01,0.55));
#636=LINE('',#635,#634);
#637=CARTESIAN_POINT('',(-6.4,1.01,0.23));
#638=VERTEX_POINT('',#637);
#639=EDGE_CURVE('E693',#638,#614,#636,.T.);
#640=ORIENTED_EDGE('',*,*,#639,.F.);
#641=DIRECTION('',(-1.,0.,0.));
#642=VECTOR('',#641,1.);
#643=CARTESIAN_POINT('',(-6.4,1.01,0.23));
#644=LINE('',#643,#642);
#645=EDGE_CURVE('E736',#638,#188,#644,.T.);
#646=ORIENTED_EDGE('',*,*,#645,.T.);
#647=EDGE_LOOP('',(#631,#632,#640,#646));
#648=FACE_BOUND('',#647,.T.);
#649=ADVANCED_FACE('F515',(#648),#630,.F.);
#650=CARTESIAN_POINT('',(-6.4,1.01,0.23));
#651=DIRECTION('',(0.,0.,1.));
#652=DIRECTION('',(0.,-1.,0.));
#653=AXIS2_PLACEMENT_3D('',#650,#651,#652);
#654=PLANE('',#653);
#655=ORIENTED_EDGE('',*,*,#189,.T.);
#656=ORIENTED_EDGE('',*,*,#645,.F.);
#657=DIRECTION('',(0.,1.,0.));
#658=VECTOR('',#657,1.);
#659=CARTESIAN_POINT('',(-6.4,1.01,0.23));
#660=LINE('',#659,#658);
#661=EDGE_CURVE('E689',#509,#638,#660,.T.);
#662=ORIENTED_EDGE('',*,*,#661,.F.);
#663=ORIENTED_EDGE('',*,*,#510,.T.);
#664=EDGE_LOOP('',(#655,#656,#662,#663));
#665=FACE_BOUND('',#664,.T.);
#666=ADVANCED_FACE('F497',(#665),#654,.F.);
#667=CARTESIAN_POINT('',(-6.4,-1.52,0.));
#668=DIRECTION('',(-1.,0.,0.));
#669=DIRECTION('',(0.,0.,1.));
#670=AXIS2_PLACEMENT_3D('',#667,#668,#669);
#671=PLANE('',#670);
#672=ORIENTED_EDGE('',*,*,#519,.T.);
#673=ORIENTED_EDGE('',*,*,#661,.T.);
#674=ORIENTED_EDGE('',*,*,#639,.T.);
#675=ORIENTED_EDGE('',*,*,#615,.T.);
#676=ORIENTED_EDGE('',*,*,#591,.T.);
#677=ORIENTED_EDGE('',*,*,#567,.T.);
#678=ORIENTED_EDGE('',*,*,#543,.T.);
#679=EDGE_LOOP('',(#672,#673,#674,#675,#676,#677,#678));
#680=FACE_BOUND('',#679,.T.);
#681=ADVANCED_FACE('F494',(#680),#671,.T.);
#682=CARTESIAN_POINT('',(6.725,0.,0.));
#683=DIRECTION('',(-1.,0.,0.));
#684=DIRECTION('',(0.,-1.,0.));
#685=AXIS2_PLACEMENT_3D('',#682,#683,#684);
#686=CONICAL_SURFACE('',#685,1.25,0.785398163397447);
#687=ORIENTED_EDGE('',*,*,#493,.F.);
#688=EDGE_LOOP('',(#687));
#689=FACE_BOUND('',#688,.T.);
#690=ORIENTED_EDGE('',*,*,#473,.F.);
#691=EDGE_LOOP('',(#690));
#692=FACE_BOUND('',#691,.T.);
#693=ADVANCED_FACE('F41',(#689,#692),#686,.T.);
#694=CARTESIAN_POINT('',(-6.4,-0.977863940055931,0.480743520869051));
#695=DIRECTION('',(0.,-1.,0.));
#696=DIRECTION('',(0.,0.,-1.));
#697=AXIS2_PLACEMENT_3D('',#694,#695,#696);
#698=PLANE('',#697);
#699=ORIENTED_EDGE('',*,*,#256,.T.);
#700=DIRECTION('',(-1.,0.,0.));
#701=VECTOR('',#700,1.);
#702=CARTESIAN_POINT('',(-6.4,-0.977863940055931,1.5996152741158));
#703=LINE('',#702,#701);
#704=CARTESIAN_POINT('',(-6.4,-0.977863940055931,1.5996152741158));
#705=VERTEX_POINT('',#704);
#706=EDGE_CURVE('E683',#705,#245,#703,.T.);
#707=ORIENTED_EDGE('',*,*,#706,.F.);
#708=DIRECTION('',(0.,0.,1.));
#709=VECTOR('',#708,1.);
#710=CARTESIAN_POINT('',(-6.4,-0.977863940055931,0.480743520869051));
#711=LINE('',#710,#709);
#712=CARTESIAN_POINT('',(-6.4,-0.977863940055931,0.480743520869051));
#713=VERTEX_POINT('',#712);
#714=EDGE_CURVE('E452',#713,#705,#711,.T.);
#715=ORIENTED_EDGE('',*,*,#714,.F.);
#716=DIRECTION('',(-1.,0.,0.));
#717=VECTOR('',#716,1.);
#718=CARTESIAN_POINT('',(-6.4,-0.977863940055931,0.480743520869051));
#719=LINE('',#718,#717);
#720=EDGE_CURVE('E650',#713,#255,#719,.T.);
#721=ORIENTED_EDGE('',*,*,#720,.T.);
#722=EDGE_LOOP('',(#699,#707,#715,#721));
#723=FACE_BOUND('',#722,.T.);
#724=ADVANCED_FACE('F489',(#723),#698,.F.);
#725=CARTESIAN_POINT('',(-6.4,-0.632409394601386,0.480743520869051));
#726=DIRECTION('',(0.,0.,-1.));
#727=DIRECTION('',(-1.,0.,0.));
#728=AXIS2_PLACEMENT_3D('',#725,#726,#727);
#729=PLANE('',#728);
#730=ORIENTED_EDGE('',*,*,#264,.T.);
#731=ORIENTED_EDGE('',*,*,#720,.F.);
#732=DIRECTION('',(0.,-1.,0.));
#733=VECTOR('',#732,1.);
#734=CARTESIAN_POINT('',(-6.4,-0.632409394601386,0.480743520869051));
#735=LINE('',#734,#733);
#736=CARTESIAN_POINT('',(-6.4,-0.632409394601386,0.480743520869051));
#737=VERTEX_POINT('',#736);
#738=EDGE_CURVE('E685',#737,#713,#735,.T.);
#739=ORIENTED_EDGE('',*,*,#738,.F.);
#740=DIRECTION('',(-1.,0.,0.));
#741=VECTOR('',#740,1.);
#742=CARTESIAN_POINT('',(-6.4,-0.632409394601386,0.480743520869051));
#743=LINE('',#742,#741);
#744=EDGE_CURVE('E653',#737,#263,#743,.T.);
#745=ORIENTED_EDGE('',*,*,#744,.T.);
#746=EDGE_LOOP('',(#730,#731,#739,#745));
#747=FACE_BOUND('',#746,.T.);
#748=ADVANCED_FACE('F492',(#747),#729,.F.);
#749=CARTESIAN_POINT('',(-6.4,-0.632409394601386,1.12731413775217));
#750=DIRECTION('',(0.,1.,0.));
#751=DIRECTION('',(0.,0.,1.));
#752=AXIS2_PLACEMENT_3D('',#749,#750,#751);
#753=PLANE('',#752);
#754=ORIENTED_EDGE('',*,*,#272,.T.);
#755=ORIENTED_EDGE('',*,*,#744,.F.);
#756=DIRECTION('',(0.,0.,-1.));
#757=VECTOR('',#756,1.);
#758=CARTESIAN_POINT('',(-6.4,-0.632409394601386,1.12731413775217));
#759=LINE('',#758,#757);
#760=CARTESIAN_POINT('',(-6.4,-0.632409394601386,1.12731413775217));
#761=VERTEX_POINT('',#760);
#762=EDGE_CURVE('E1309',#761,#737,#759,.T.);
#763=ORIENTED_EDGE('',*,*,#762,.F.);
#764=DIRECTION('',(-1.,0.,0.));
#765=VECTOR('',#764,1.);
#766=CARTESIAN_POINT('',(-6.4,-0.632409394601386,1.12731413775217));
#767=LINE('',#766,#765);
#768=EDGE_CURVE('E655',#761,#271,#767,.T.);
#769=ORIENTED_EDGE('',*,*,#768,.T.);
#770=EDGE_LOOP('',(#754,#755,#763,#769));
#771=FACE_BOUND('',#770,.T.);
#772=ADVANCED_FACE('F764',(#771),#753,.F.);
#773=CARTESIAN_POINT('',(-6.4,-0.0402016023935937,0.661567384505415));
#774=DIRECTION('',(0.,-0.618183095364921,-0.786034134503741));
#775=DIRECTION('',(0.,0.786034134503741,-0.618183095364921));
#776=AXIS2_PLACEMENT_3D('',#773,#774,#775);
#777=PLANE('',#776);
#778=ORIENTED_EDGE('',*,*,#280,.T.);
#779=ORIENTED_EDGE('',*,*,#768,.F.);
#780=DIRECTION('',(0.,-0.786034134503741,0.618183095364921));
#781=VECTOR('',#780,1.);
#782=CARTESIAN_POINT('',(-6.4,-0.0402016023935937,0.661567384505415));
#783=LINE('',#782,#781);
#784=CARTESIAN_POINT('',(-6.4,-0.0402016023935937,0.661567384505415));
#785=VERTEX_POINT('',#784);
#786=EDGE_CURVE('E1301',#785,#761,#783,.T.);
#787=ORIENTED_EDGE('',*,*,#786,.F.);
#788=DIRECTION('',(-1.,0.,0.));
#789=VECTOR('',#788,1.);
#790=CARTESIAN_POINT('',(-6.4,-0.0402016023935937,0.661567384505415));
#791=LINE('',#790,#789);
#792=EDGE_CURVE('E657',#785,#279,#791,.T.);
#793=ORIENTED_EDGE('',*,*,#792,.T.);
#794=EDGE_LOOP('',(#778,#779,#787,#793));
#795=FACE_BOUND('',#794,.T.);
#796=ADVANCED_FACE('F772',(#795),#777,.F.);
#797=CARTESIAN_POINT('',(-6.4,0.448678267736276,0.491153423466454));
#798=CARTESIAN_POINT('',(-6.4,0.427059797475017,0.491644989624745));
#799=CARTESIAN_POINT('',(-6.4,0.383784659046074,0.492628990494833));
#800=CARTESIAN_POINT('',(-6.4,0.319017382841,0.501511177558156));
#801=CARTESIAN_POINT('',(-6.4,0.254580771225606,0.515824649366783));
#802=CARTESIAN_POINT('',(-6.4,0.190786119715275,0.535482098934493));
#803=CARTESIAN_POINT('',(-6.4,0.128738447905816,0.559901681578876));
#804=CARTESIAN_POINT('',(-6.4,0.0692875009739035,0.589209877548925));
#805=CARTESIAN_POINT('',(-6.4,0.0124069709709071,0.622287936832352));
#806=CARTESIAN_POINT('',(-6.4,-0.0226989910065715,0.648499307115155));
#807=CARTESIAN_POINT('',(-6.4,-0.0402016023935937,0.661567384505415));
#808=B_SPLINE_CURVE_WITH_KNOTS('',3,(#797,#798,#799,#800,#801,#802,#803,#804,#805,#806,#807),
.UNSPECIFIED.,.F.,.F.,(4,1,1,1,1,1,1,1,4),(0.,0.123046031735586,0.246309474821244,
0.371480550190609,0.498560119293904,0.626024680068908,0.750715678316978,0.875715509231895,1.),.UNSPECIFIED.);
#809=DIRECTION('',(-1.,0.,0.));
#810=VECTOR('',#809,1.);
#811=SURFACE_OF_LINEAR_EXTRUSION('',#808,#810);
#812=ORIENTED_EDGE('',*,*,#296,.T.);
#813=ORIENTED_EDGE('',*,*,#792,.F.);
#814=CARTESIAN_POINT('',(-6.4,0.448678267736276,0.491153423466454));
#815=VERTEX_POINT('',#814);
#816=EDGE_CURVE('E1294',#815,#785,#808,.T.);
#817=ORIENTED_EDGE('',*,*,#816,.F.);
#818=DIRECTION('',(-1.,0.,0.));
#819=VECTOR('',#818,1.);
#820=CARTESIAN_POINT('',(-6.4,0.448678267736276,0.491153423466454));
#821=LINE('',#820,#819);
#822=EDGE_CURVE('E659',#815,#295,#821,.T.);
#823=ORIENTED_EDGE('',*,*,#822,.T.);
#824=EDGE_LOOP('',(#812,#813,#817,#823));
#825=FACE_BOUND('',#824,.T.);
#826=ADVANCED_FACE('F780',(#825),#811,.F.);
#827=CARTESIAN_POINT('',(-6.4,0.450220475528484,0.491153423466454));
#828=DIRECTION('',(0.,0.,-1.));
#829=DIRECTION('',(-1.,0.,0.));
#830=AXIS2_PLACEMENT_3D('',#827,#828,#829);
#831=PLANE('',#830);
#832=ORIENTED_EDGE('',*,*,#304,.T.);
#833=ORIENTED_EDGE('',*,*,#822,.F.);
#834=DIRECTION('',(0.,-1.,0.));
#835=VECTOR('',#834,1.);
#836=CARTESIAN_POINT('',(-6.4,0.450220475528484,0.491153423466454));
#837=LINE('',#836,#835);
#838=CARTESIAN_POINT('',(-6.4,0.450220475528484,0.491153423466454));
#839=VERTEX_POINT('',#838);
#840=EDGE_CURVE('E1302',#839,#815,#837,.T.);
#841=ORIENTED_EDGE('',*,*,#840,.F.);
#842=DIRECTION('',(-1.,0.,0.));
#843=VECTOR('',#842,1.);
#844=CARTESIAN_POINT('',(-6.4,0.450220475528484,0.491153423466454));
#845=LINE('',#844,#843);
#846=EDGE_CURVE('E661',#839,#303,#845,.T.);
#847=ORIENTED_EDGE('',*,*,#846,.T.);
#848=EDGE_LOOP('',(#832,#833,#841,#847));
#849=FACE_BOUND('',#848,.T.);
#850=ADVANCED_FACE('F788',(#849),#831,.F.);
#851=CARTESIAN_POINT('',(-6.4,0.946811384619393,1.05058930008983));
#852=CARTESIAN_POINT('',(-6.4,0.946504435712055,1.02898096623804));
#853=CARTESIAN_POINT('',(-6.4,0.945907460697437,0.986955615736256));
#854=CARTESIAN_POINT('',(-6.4,0.939463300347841,0.925773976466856));
#855=CARTESIAN_POINT('',(-6.4,0.929737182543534,0.868208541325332));
#856=CARTESIAN_POINT('',(-6.4,0.915508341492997,0.814351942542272));
#857=CARTESIAN_POINT('',(-6.4,0.896948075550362,0.764420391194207));
#858=CARTESIAN_POINT('',(-6.4,0.874568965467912,0.718264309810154));
#859=CARTESIAN_POINT('',(-6.4,0.848180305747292,0.67578721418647));
#860=CARTESIAN_POINT('',(-6.4,0.817725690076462,0.637314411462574));
#861=CARTESIAN_POINT('',(-6.4,0.783758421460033,0.602698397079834));
#862=CARTESIAN_POINT('',(-6.4,0.745933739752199,0.572903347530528));
#863=CARTESIAN_POINT('',(-6.4,0.705016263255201,0.547110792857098));
#864=CARTESIAN_POINT('',(-6.4,0.660212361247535,0.526948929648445));
#865=CARTESIAN_POINT('',(-6.4,0.612575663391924,0.51035006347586));
#866=CARTESIAN_POINT('',(-6.4,0.561252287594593,0.499602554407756));
#867=CARTESIAN_POINT('',(-6.4,0.506846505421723,0.492360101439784));
#868=CARTESIAN_POINT('',(-6.4,0.469394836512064,0.491562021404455));
#869=CARTESIAN_POINT('',(-6.4,0.450220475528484,0.491153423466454));
#870=B_SPLINE_CURVE_WITH_KNOTS('',3,(#851,#852,#853,#854,#855,#856,#857,#858,#859,#860,#861,
#862,#863,#864,#865,#866,#867,#868,#869),.UNSPECIFIED.,.F.,.F.,(4,1,1,1,1,1,1,1,1,1,1,1,1,1,1,1,
4),(0.,0.0762312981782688,0.148259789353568,0.216860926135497,0.28210063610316,
0.344528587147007,0.404571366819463,0.462840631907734,0.520642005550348,0.577409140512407,
0.633580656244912,0.690215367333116,0.747647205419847,0.806597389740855,0.867894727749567,
0.932365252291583,1.),.UNSPECIFIED.);
#871=DIRECTION('',(-1.,0.,0.));
#872=VECTOR('',#871,1.);
#873=SURFACE_OF_LINEAR_EXTRUSION('',#870,#872);
#874=ORIENTED_EDGE('',*,*,#328,.T.);
#875=ORIENTED_EDGE('',*,*,#846,.F.);
#876=CARTESIAN_POINT('',(-6.4,0.946811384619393,1.05058930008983));
#877=VERTEX_POINT('',#876);
#878=EDGE_CURVE('E1345',#877,#839,#870,.T.);
#879=ORIENTED_EDGE('',*,*,#878,.F.);
#880=DIRECTION('',(-1.,0.,0.));
#881=VECTOR('',#880,1.);
#882=CARTESIAN_POINT('',(-6.4,0.946811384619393,1.05058930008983));
#883=LINE('',#882,#881);
#884=EDGE_CURVE('E663',#877,#327,#883,.T.);
#885=ORIENTED_EDGE('',*,*,#884,.T.);
#886=EDGE_LOOP('',(#874,#875,#879,#885));
#887=FACE_BOUND('',#886,.T.);
#888=ADVANCED_FACE('F796',(#887),#873,.F.);
#889=CARTESIAN_POINT('',(-6.4,0.376580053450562,1.62313394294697));
#890=CARTESIAN_POINT('',(-6.4,0.398603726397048,1.62133041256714));
#891=CARTESIAN_POINT('',(-6.4,0.441593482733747,1.61780995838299));
#892=CARTESIAN_POINT('',(-6.4,0.503780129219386,1.60626838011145));
#893=CARTESIAN_POINT('',(-6.4,0.562355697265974,1.59135134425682));
#894=CARTESIAN_POINT('',(-6.4,0.617308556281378,1.57237486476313));
#895=CARTESIAN_POINT('',(-6.4,0.668002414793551,1.54799002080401));
#896=CARTESIAN_POINT('',(-6.4,0.715497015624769,1.52059290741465));
#897=CARTESIAN_POINT('',(-6.4,0.758323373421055,1.48764104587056));
#898=CARTESIAN_POINT('',(-6.4,0.797914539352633,1.45157061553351));
#899=CARTESIAN_POINT('',(-6.4,0.832785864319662,1.41139460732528));
#900=CARTESIAN_POINT('',(-6.4,0.863547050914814,1.36855594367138));
#901=CARTESIAN_POINT('',(-6.4,0.889145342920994,1.3224068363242));
#902=CARTESIAN_POINT('',(-6.4,0.910380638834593,1.273648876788));
#903=CARTESIAN_POINT('',(-6.4,0.926497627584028,1.22174147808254));
#904=CARTESIAN_POINT('',(-6.4,0.938570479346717,1.1673626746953));
#905=CARTESIAN_POINT('',(-6.4,0.945532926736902,1.10988829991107));
#906=CARTESIAN_POINT('',(-6.4,0.94637874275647,1.07065662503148));
#907=CARTESIAN_POINT('',(-6.4,0.946811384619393,1.05058930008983));
#908=B_SPLINE_CURVE_WITH_KNOTS('',3,(#889,#890,#891,#892,#893,#894,#895,#896,#897,#898,#899,
#900,#901,#902,#903,#904,#905,#906,#907),.UNSPECIFIED.,.F.,.F.,(4,1,1,1,1,1,1,1,1,1,1,1,1,1,1,1,
4),(0.,0.0733268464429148,0.14313249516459,0.209679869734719,0.273918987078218,0.33576228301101,
0.396210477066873,0.45560885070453,0.514796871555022,0.573764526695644,0.631900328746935,
0.689592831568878,0.748648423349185,0.808163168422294,0.86976604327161,0.933384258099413,1.),.UNSPECIFIED.);
#909=DIRECTION('',(-1.,0.,0.));
#910=VECTOR('',#909,1.);
#911=SURFACE_OF_LINEAR_EXTRUSION('',#908,#910);
#912=ORIENTED_EDGE('',*,*,#352,.T.);
#913=ORIENTED_EDGE('',*,*,#884,.F.);
#914=CARTESIAN_POINT('',(-6.4,0.376580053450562,1.62313394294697));
#915=VERTEX_POINT('',#914);
#916=EDGE_CURVE('E1339',#915,#877,#908,.T.);
#917=ORIENTED_EDGE('',*,*,#916,.F.);
#918=DIRECTION('',(-1.,0.,0.));
#919=VECTOR('',#918,1.);
#920=CARTESIAN_POINT('',(-6.4,0.376580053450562,1.62313394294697));
#921=LINE('',#920,#919);
#922=EDGE_CURVE('E665',#915,#351,#921,.T.);
#923=ORIENTED_EDGE('',*,*,#922,.T.);
#924=EDGE_LOOP('',(#912,#913,#917,#923));
#925=FACE_BOUND('',#924,.T.);
#926=ADVANCED_FACE('F804',(#925),#911,.F.);
#927=CARTESIAN_POINT('',(-6.4,0.375423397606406,1.62313394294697));
#928=DIRECTION('',(0.,0.,1.));
#929=DIRECTION('',(1.,0.,0.));
#930=AXIS2_PLACEMENT_3D('',#927,#928,#929);
#931=PLANE('',#930);
#932=ORIENTED_EDGE('',*,*,#360,.T.);
#933=ORIENTED_EDGE('',*,*,#922,.F.);
#934=DIRECTION('',(0.,1.,0.));
#935=VECTOR('',#934,1.);
#936=CARTESIAN_POINT('',(-6.4,0.375423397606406,1.62313394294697));
#937=LINE('',#936,#935);
#938=CARTESIAN_POINT('',(-6.4,0.375423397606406,1.62313394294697));
#939=VERTEX_POINT('',#938);
#940=EDGE_CURVE('E1346',#939,#915,#937,.T.);
#941=ORIENTED_EDGE('',*,*,#940,.F.);
#942=DIRECTION('',(-1.,0.,0.));
#943=VECTOR('',#942,1.);
#944=CARTESIAN_POINT('',(-6.4,0.375423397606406,1.62313394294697));
#945=LINE('',#944,#943);
#946=EDGE_CURVE('E667',#939,#359,#945,.T.);
#947=ORIENTED_EDGE('',*,*,#946,.T.);
#948=EDGE_LOOP('',(#932,#933,#941,#947));
#949=FACE_BOUND('',#948,.T.);
#950=ADVANCED_FACE('F812',(#949),#931,.F.);
#951=CARTESIAN_POINT('',(-6.4,0.375423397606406,1.25763069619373));
#952=DIRECTION('',(0.,-1.,0.));
#953=DIRECTION('',(0.,0.,-1.));
#954=AXIS2_PLACEMENT_3D('',#951,#952,#953);
#955=PLANE('',#954);
#956=ORIENTED_EDGE('',*,*,#368,.T.);
#957=ORIENTED_EDGE('',*,*,#946,.F.);
#958=DIRECTION('',(0.,0.,1.));
#959=VECTOR('',#958,1.);
#960=CARTESIAN_POINT('',(-6.4,0.375423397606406,1.25763069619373));
#961=LINE('',#960,#959);
#962=CARTESIAN_POINT('',(-6.4,0.375423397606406,1.25763069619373));
#963=VERTEX_POINT('',#962);
#964=EDGE_CURVE('E1378',#963,#939,#961,.T.);
#965=ORIENTED_EDGE('',*,*,#964,.F.);
#966=DIRECTION('',(-1.,0.,0.));
#967=VECTOR('',#966,1.);
#968=CARTESIAN_POINT('',(-6.4,0.375423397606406,1.25763069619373));
#969=LINE('',#968,#967);
#970=EDGE_CURVE('E669',#963,#367,#969,.T.);
#971=ORIENTED_EDGE('',*,*,#970,.T.);
#972=EDGE_LOOP('',(#956,#957,#965,#971));
#973=FACE_BOUND('',#972,.T.);
#974=ADVANCED_FACE('F820',(#973),#955,.F.);
#975=CARTESIAN_POINT('',(-6.4,0.376580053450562,1.25763069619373));
#976=DIRECTION('',(0.,0.,-1.));
#977=DIRECTION('',(-1.,0.,0.));
#978=AXIS2_PLACEMENT_3D('',#975,#976,#977);
#979=PLANE('',#978);
#980=ORIENTED_EDGE('',*,*,#376,.T.);
#981=ORIENTED_EDGE('',*,*,#970,.F.);
#982=DIRECTION('',(0.,-1.,0.));
#983=VECTOR('',#982,1.);
#984=CARTESIAN_POINT('',(-6.4,0.376580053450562,1.25763069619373));
#985=LINE('',#984,#983);
#986=CARTESIAN_POINT('',(-6.4,0.376580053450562,1.25763069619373));
#987=VERTEX_POINT('',#986);
#988=EDGE_CURVE('E1326',#987,#963,#985,.T.);
#989=ORIENTED_EDGE('',*,*,#988,.F.);
#990=DIRECTION('',(-1.,0.,0.));
#991=VECTOR('',#990,1.);
#992=CARTESIAN_POINT('',(-6.4,0.376580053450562,1.25763069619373));
#993=LINE('',#992,#991);
#994=EDGE_CURVE('E671',#987,#375,#993,.T.);
#995=ORIENTED_EDGE('',*,*,#994,.T.);
#996=EDGE_LOOP('',(#980,#981,#989,#995));
#997=FACE_BOUND('',#996,.T.);
#998=ADVANCED_FACE('F828',(#997),#979,.F.);
#999=CARTESIAN_POINT('',(-6.4,0.601356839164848,1.04789043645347));
#1000=CARTESIAN_POINT('',(-6.4,0.600811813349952,1.06185822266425));
#1001=CARTESIAN_POINT('',(-6.4,0.599752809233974,1.08899811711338));
#1002=CARTESIAN_POINT('',(-6.4,0.588016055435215,1.12741926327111));
#1003=CARTESIAN_POINT('',(-6.4,0.569606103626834,1.16204046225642));
#1004=CARTESIAN_POINT('',(-6.4,0.543337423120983,1.19188668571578));
#1005=CARTESIAN_POINT('',(-6.4,0.510356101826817,1.21660161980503));
#1006=CARTESIAN_POINT('',(-6.4,0.471517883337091,1.23666018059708));
#1007=CARTESIAN_POINT('',(-6.4,0.426121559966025,1.25028380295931));
#1008=CARTESIAN_POINT('',(-6.4,0.393625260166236,1.25510293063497));
#1009=CARTESIAN_POINT('',(-6.4,0.376580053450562,1.25763069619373));
#1010=B_SPLINE_CURVE_WITH_KNOTS('',3,(#999,#1000,#1001,#1002,#1003,#1004,#1005,#1006,#1007,
#1008,#1009),.UNSPECIFIED.,.F.,.F.,(4,1,1,1,1,1,1,1,4),(0.,0.122603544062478,0.238222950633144,
0.350089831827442,0.465559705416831,0.58502806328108,0.711014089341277,0.848418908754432,1.),.UNSPECIFIED.);
#1011=DIRECTION('',(-1.,0.,0.));
#1012=VECTOR('',#1011,1.);
#1013=SURFACE_OF_LINEAR_EXTRUSION('',#1010,#1012);
#1014=ORIENTED_EDGE('',*,*,#392,.T.);
#1015=ORIENTED_EDGE('',*,*,#994,.F.);
#1016=CARTESIAN_POINT('',(-6.4,0.601356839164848,1.04789043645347));
#1017=VERTEX_POINT('',#1016);
#1018=EDGE_CURVE('E1324',#1017,#987,#1010,.T.);
#1019=ORIENTED_EDGE('',*,*,#1018,.F.);
#1020=DIRECTION('',(-1.,0.,0.));
#1021=VECTOR('',#1020,1.);
#1022=CARTESIAN_POINT('',(-6.4,0.601356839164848,1.04789043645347));
#1023=LINE('',#1022,#1021);
#1024=EDGE_CURVE('E673',#1017,#391,#1023,.T.);
#1025=ORIENTED_EDGE('',*,*,#1024,.T.);
#1026=EDGE_LOOP('',(#1014,#1015,#1019,#1025));
#1027=FACE_BOUND('',#1026,.T.);
#1028=ADVANCED_FACE('F836',(#1027),#1013,.F.);
#1029=CARTESIAN_POINT('',(-6.4,0.440196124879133,0.858198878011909));
#1030=CARTESIAN_POINT('',(-6.4,0.452344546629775,0.858725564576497));
#1031=CARTESIAN_POINT('',(-6.4,0.475618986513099,0.859734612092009));
#1032=CARTESIAN_POINT('',(-6.4,0.508413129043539,0.869241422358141));
#1033=CARTESIAN_POINT('',(-6.4,0.536971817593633,0.884822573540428));
#1034=CARTESIAN_POINT('',(-6.4,0.560561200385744,0.907138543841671));
#1035=CARTESIAN_POINT('',(-6.4,0.579218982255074,0.934920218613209));
#1036=CARTESIAN_POINT('',(-6.4,0.592367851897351,0.968161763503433));
#1037=CARTESIAN_POINT('',(-6.4,0.59990788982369,1.00642824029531));
#1038=CARTESIAN_POINT('',(-6.4,0.600857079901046,1.03358964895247));
#1039=CARTESIAN_POINT('',(-6.4,0.601356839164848,1.04789043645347));
#1040=B_SPLINE_CURVE_WITH_KNOTS('',3,(#1029,#1030,#1031,#1032,#1033,#1034,#1035,#1036,#1037,
#1038,#1039),.UNSPECIFIED.,.F.,.F.,(4,1,1,1,1,1,1,1,4),(0.,0.128749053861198,0.246662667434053,
0.359069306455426,0.471077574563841,0.588039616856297,0.711712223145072,0.848213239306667,1.),.UNSPECIFIED.);
#1041=DIRECTION('',(-1.,0.,0.));
#1042=VECTOR('',#1041,1.);
#1043=SURFACE_OF_LINEAR_EXTRUSION('',#1040,#1042);
#1044=ORIENTED_EDGE('',*,*,#408,.T.);
#1045=ORIENTED_EDGE('',*,*,#1024,.F.);
#1046=CARTESIAN_POINT('',(-6.4,0.440196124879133,0.858198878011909));
#1047=VERTEX_POINT('',#1046);
#1048=EDGE_CURVE('E1323',#1047,#1017,#1040,.T.);
#1049=ORIENTED_EDGE('',*,*,#1048,.F.);
#1050=DIRECTION('',(-1.,0.,0.));
#1051=VECTOR('',#1050,1.);
#1052=CARTESIAN_POINT('',(-6.4,0.440196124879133,0.858198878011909));
#1053=LINE('',#1052,#1051);
#1054=EDGE_CURVE('E675',#1047,#407,#1053,.T.);
#1055=ORIENTED_EDGE('',*,*,#1054,.T.);
#1056=EDGE_LOOP('',(#1044,#1045,#1049,#1055));
#1057=FACE_BOUND('',#1056,.T.);
#1058=ADVANCED_FACE('F844',(#1057),#1043,.F.);
#1059=CARTESIAN_POINT('',(-6.4,0.43749726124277,0.858198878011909));
#1060=DIRECTION('',(0.,0.,1.));
#1061=DIRECTION('',(1.,0.,0.));
#1062=AXIS2_PLACEMENT_3D('',#1059,#1060,#1061);
#1063=PLANE('',#1062);
#1064=ORIENTED_EDGE('',*,*,#416,.T.);
#1065=ORIENTED_EDGE('',*,*,#1054,.F.);
#1066=DIRECTION('',(0.,1.,0.));
#1067=VECTOR('',#1066,1.);
#1068=CARTESIAN_POINT('',(-6.4,0.43749726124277,0.858198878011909));
#1069=LINE('',#1068,#1067);
#1070=CARTESIAN_POINT('',(-6.4,0.43749726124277,0.858198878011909));
#1071=VERTEX_POINT('',#1070);
#1072=EDGE_CURVE('E468',#1071,#1047,#1069,.T.);
#1073=ORIENTED_EDGE('',*,*,#1072,.F.);
#1074=DIRECTION('',(-1.,0.,0.));
#1075=VECTOR('',#1074,1.);
#1076=CARTESIAN_POINT('',(-6.4,0.43749726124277,0.858198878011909));
#1077=LINE('',#1076,#1075);
#1078=EDGE_CURVE('E677',#1071,#415,#1077,.T.);
#1079=ORIENTED_EDGE('',*,*,#1078,.T.);
#1080=EDGE_LOOP('',(#1064,#1065,#1073,#1079));
#1081=FACE_BOUND('',#1080,.T.);
#1082=ADVANCED_FACE('F479',(#1081),#1063,.F.);
#1083=CARTESIAN_POINT('',(-6.4,0.205394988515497,0.950345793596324));
#1084=CARTESIAN_POINT('',(-6.4,0.224556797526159,0.93674672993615));
#1085=CARTESIAN_POINT('',(-6.4,0.261893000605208,0.910249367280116));
#1086=CARTESIAN_POINT('',(-6.4,0.313166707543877,0.88626721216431));
#1087=CARTESIAN_POINT('',(-6.4,0.353365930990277,0.87132732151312));
#1088=CARTESIAN_POINT('',(-6.4,0.382518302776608,0.86420729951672));
#1089=CARTESIAN_POINT('',(-6.4,0.410332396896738,0.859128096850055));
#1090=CARTESIAN_POINT('',(-6.4,0.42860852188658,0.858502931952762));
#1091=CARTESIAN_POINT('',(-6.4,0.43749726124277,0.858198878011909));
#1092=B_SPLINE_CURVE_WITH_KNOTS('',3,(#1083,#1084,#1085,#1086,#1087,#1088,#1089,#1090,#1091),
.UNSPECIFIED.,.F.,.F.,(4,1,1,1,1,1,4),(0.,0.27737542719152,0.540457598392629,0.666416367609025,
0.784009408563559,0.894951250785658,1.),.UNSPECIFIED.);
#1093=DIRECTION('',(-1.,0.,0.));
#1094=VECTOR('',#1093,1.);
#1095=SURFACE_OF_LINEAR_EXTRUSION('',#1092,#1094);
#1096=ORIENTED_EDGE('',*,*,#430,.T.);
#1097=ORIENTED_EDGE('',*,*,#1078,.F.);
#1098=CARTESIAN_POINT('',(-6.4,0.205394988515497,0.950345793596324));
#1099=VERTEX_POINT('',#1098);
#1100=EDGE_CURVE('E462',#1099,#1071,#1092,.T.);
#1101=ORIENTED_EDGE('',*,*,#1100,.F.);
#1102=DIRECTION('',(-1.,0.,0.));
#1103=VECTOR('',#1102,1.);
#1104=CARTESIAN_POINT('',(-6.4,0.205394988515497,0.950345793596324));
#1105=LINE('',#1104,#1103);
#1106=EDGE_CURVE('E679',#1099,#429,#1105,.T.);
#1107=ORIENTED_EDGE('',*,*,#1106,.T.);
#1108=EDGE_LOOP('',(#1096,#1097,#1101,#1107));
#1109=FACE_BOUND('',#1108,.T.);
#1110=ADVANCED_FACE('F474',(#1109),#1095,.F.);
#1111=CARTESIAN_POINT('',(-6.4,-0.654771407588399,1.5996152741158));
#1112=DIRECTION('',(0.,0.602458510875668,0.798150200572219));
#1113=DIRECTION('',(0.,-0.798150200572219,0.602458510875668));
#1114=AXIS2_PLACEMENT_3D('',#1111,#1112,#1113);
#1115=PLANE('',#1114);
#1116=ORIENTED_EDGE('',*,*,#436,.T.);
#1117=ORIENTED_EDGE('',*,*,#1106,.F.);
#1118=DIRECTION('',(0.,0.798150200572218,-0.602458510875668));
#1119=VECTOR('',#1118,1.);
#1120=CARTESIAN_POINT('',(-6.4,-0.654771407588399,1.5996152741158));
#1121=LINE('',#1120,#1119);
#1122=CARTESIAN_POINT('',(-6.4,-0.654771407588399,1.5996152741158));
#1123=VERTEX_POINT('',#1122);
#1124=EDGE_CURVE('E459',#1123,#1099,#1121,.T.);
#1125=ORIENTED_EDGE('',*,*,#1124,.F.);
#1126=DIRECTION('',(-1.,0.,0.));
#1127=VECTOR('',#1126,1.);
#1128=CARTESIAN_POINT('',(-6.4,-0.654771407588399,1.5996152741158));
#1129=LINE('',#1128,#1127);
#1130=EDGE_CURVE('E681',#1123,#247,#1129,.T.);
#1131=ORIENTED_EDGE('',*,*,#1130,.T.);
#1132=EDGE_LOOP('',(#1116,#1117,#1125,#1131));
#1133=FACE_BOUND('',#1132,.T.);
#1134=ADVANCED_FACE('F478',(#1133),#1115,.F.);
#1135=CARTESIAN_POINT('',(-6.4,-0.977863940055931,1.5996152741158));
#1136=DIRECTION('',(0.,0.,1.));
#1137=DIRECTION('',(1.,0.,0.));
#1138=AXIS2_PLACEMENT_3D('',#1135,#1136,#1137);
#1139=PLANE('',#1138);
#1140=ORIENTED_EDGE('',*,*,#248,.T.);
#1141=ORIENTED_EDGE('',*,*,#1130,.F.);
#1142=DIRECTION('',(0.,1.,0.));
#1143=VECTOR('',#1142,1.);
#1144=CARTESIAN_POINT('',(-6.4,-0.977863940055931,1.5996152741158));
#1145=LINE('',#1144,#1143);
#1146=EDGE_CURVE('E455',#705,#1123,#1145,.T.);
#1147=ORIENTED_EDGE('',*,*,#1146,.F.);
#1148=ORIENTED_EDGE('',*,*,#706,.T.);
#1149=EDGE_LOOP('',(#1140,#1141,#1147,#1148));
#1150=FACE_BOUND('',#1149,.T.);
#1151=ADVANCED_FACE('F484',(#1150),#1139,.F.);
#1152=CARTESIAN_POINT('',(-6.4,0.314641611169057,0.886407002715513));
#1153=DIRECTION('',(-1.,0.,-1.39822615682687E-13));
#1154=DIRECTION('',(-1.39822615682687E-13,0.,1.));
#1155=AXIS2_PLACEMENT_3D('',#1152,#1153,#1154);
#1156=PLANE('',#1155);
#1157=ORIENTED_EDGE('',*,*,#714,.T.);
#1158=ORIENTED_EDGE('',*,*,#1146,.T.);
#1159=ORIENTED_EDGE('',*,*,#1124,.T.);
#1160=ORIENTED_EDGE('',*,*,#1100,.T.);
#1161=ORIENTED_EDGE('',*,*,#1072,.T.);
#1162=ORIENTED_EDGE('',*,*,#1048,.T.);
#1163=ORIENTED_EDGE('',*,*,#1018,.T.);
#1164=ORIENTED_EDGE('',*,*,#988,.T.);
#1165=ORIENTED_EDGE('',*,*,#964,.T.);
#1166=ORIENTED_EDGE('',*,*,#940,.T.);
#1167=ORIENTED_EDGE('',*,*,#916,.T.);
#1168=ORIENTED_EDGE('',*,*,#878,.T.);
#1169=ORIENTED_EDGE('',*,*,#840,.T.);
#1170=ORIENTED_EDGE('',*,*,#816,.T.);
#1171=ORIENTED_EDGE('',*,*,#786,.T.);
#1172=ORIENTED_EDGE('',*,*,#762,.T.);
#1173=ORIENTED_EDGE('',*,*,#738,.T.);
#1174=EDGE_LOOP('',(#1157,#1158,#1159,#1160,#1161,#1162,#1163,#1164,#1165,#1166,#1167,#1168,
#1169,#1170,#1171,#1172,#1173));
#1175=FACE_BOUND('',#1174,.T.);
#1176=ADVANCED_FACE('F346',(#1175),#1156,.T.);
#1177=CARTESIAN_POINT('',(-6.4,-0.842633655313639,-1.40323406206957));
#1178=DIRECTION('',(1.,0.,6.96535986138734E-13));
#1179=DIRECTION('',(6.96535986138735E-13,0.,-1.));
#1180=AXIS2_PLACEMENT_3D('',#1177,#1178,#1179);
#1181=PLANE('',#1180);
#1182=CARTESIAN_POINT('',(-6.4,-0.416885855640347,-1.54261768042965));
#1183=CARTESIAN_POINT('',(-6.4,-0.43939637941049,-1.54220300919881));
#1184=CARTESIAN_POINT('',(-6.4,-0.483372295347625,-1.54139291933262));
#1185=CARTESIAN_POINT('',(-6.4,-0.547285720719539,-1.53424727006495));
#1186=CARTESIAN_POINT('',(-6.4,-0.607446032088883,-1.52329861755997));
#1187=CARTESIAN_POINT('',(-6.4,-0.663632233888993,-1.50749191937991));
#1188=CARTESIAN_POINT('',(-6.4,-0.715983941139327,-1.48704519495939));
#1189=CARTESIAN_POINT('',(-6.4,-0.764518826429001,-1.46192670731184));
#1190=CARTESIAN_POINT('',(-6.4,-0.808997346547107,-1.43202089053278));
#1191=CARTESIAN_POINT('',(-6.4,-0.8497419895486,-1.39817826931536));
#1192=CARTESIAN_POINT('',(-6.4,-0.885595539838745,-1.35976917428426));
#1193=CARTESIAN_POINT('',(-6.4,-0.917099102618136,-1.3178237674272));
#1194=CARTESIAN_POINT('',(-6.4,-0.944015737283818,-1.27219444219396));
#1195=CARTESIAN_POINT('',(-6.4,-0.964954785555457,-1.22220565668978));
#1196=CARTESIAN_POINT('',(-6.4,-0.982143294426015,-1.16900100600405));
#1197=CARTESIAN_POINT('',(-6.4,-0.993818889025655,-1.11184817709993));
#1198=CARTESIAN_POINT('',(-6.4,-1.00140955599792,-1.05124446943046));
#1199=CARTESIAN_POINT('',(-6.4,-1.0021565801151,-1.00955209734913));
#1200=CARTESIAN_POINT('',(-6.4,-1.00253926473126,-0.988193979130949));
#1201=B_SPLINE_CURVE_WITH_KNOTS('',3,(#1182,#1183,#1184,#1185,#1186,#1187,#1188,#1189,#1190,
#1191,#1192,#1193,#1194,#1195,#1196,#1197,#1198,#1199,#1200),.UNSPECIFIED.,.F.,.F.,(4,1,1,1,1,1,
1,1,1,1,1,1,1,1,1,1,4),(0.,0.0736363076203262,0.143853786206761,0.210167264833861,
0.273535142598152,0.334525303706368,0.393774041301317,0.451974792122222,0.509587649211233,
0.566708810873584,0.623480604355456,0.680964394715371,0.739551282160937,0.800463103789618,
0.863640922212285,0.930146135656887,1.),.UNSPECIFIED.);
#1202=CARTESIAN_POINT('',(-6.4,-0.416885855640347,-1.54261768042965));
#1203=VERTEX_POINT('',#1202);
#1204=CARTESIAN_POINT('',(-6.4,-1.00253926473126,-0.988193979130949));
#1205=VERTEX_POINT('',#1204);
#1206=EDGE_CURVE('E431',#1203,#1205,#1201,.T.);
#1207=ORIENTED_EDGE('',*,*,#1206,.T.);
#1208=CARTESIAN_POINT('',(-6.4,-1.00253926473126,-0.988193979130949));
#1209=CARTESIAN_POINT('',(-6.4,-1.00211098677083,-0.966842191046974));
#1210=CARTESIAN_POINT('',(-6.4,-1.00127782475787,-0.92530491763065));
#1211=CARTESIAN_POINT('',(-6.4,-0.994369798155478,-0.864879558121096));
#1212=CARTESIAN_POINT('',(-6.4,-0.982370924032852,-0.808239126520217));
#1213=CARTESIAN_POINT('',(-6.4,-0.965811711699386,-0.755134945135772));
#1214=CARTESIAN_POINT('',(-6.4,-0.944644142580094,-0.70556513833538));
#1215=CARTESIAN_POINT('',(-6.4,-0.918692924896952,-0.659749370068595));
#1216=CARTESIAN_POINT('',(-6.4,-0.887939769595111,-0.617664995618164));
#1217=CARTESIAN_POINT('',(-6.4,-0.852451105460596,-0.579524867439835));
#1218=CARTESIAN_POINT('',(-6.4,-0.812669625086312,-0.545597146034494));
#1219=CARTESIAN_POINT('',(-6.4,-0.768983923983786,-0.515962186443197));
#1220=CARTESIAN_POINT('',(-6.4,-0.721408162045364,-0.490870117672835));
#1221=CARTESIAN_POINT('',(-6.4,-0.669918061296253,-0.470519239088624));
#1222=CARTESIAN_POINT('',(-6.4,-0.614672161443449,-0.454557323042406));
#1223=CARTESIAN_POINT('',(-6.4,-0.55563240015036,-0.443761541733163));
#1224=CARTESIAN_POINT('',(-6.4,-0.492762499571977,-0.436490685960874));
#1225=CARTESIAN_POINT('',(-6.4,-0.449551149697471,-0.435713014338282));
#1226=CARTESIAN_POINT('',(-6.4,-0.42729575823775,-0.435312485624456));
#1227=B_SPLINE_CURVE_WITH_KNOTS('',3,(#1208,#1209,#1210,#1211,#1212,#1213,#1214,#1215,#1216,
#1217,#1218,#1219,#1220,#1221,#1222,#1223,#1224,#1225,#1226),.UNSPECIFIED.,.F.,.F.,(4,1,1,1,1,1,
1,1,1,1,1,1,1,1,1,1,4),(0.,0.0706034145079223,0.137350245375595,0.200790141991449,
0.261822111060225,0.321037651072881,0.378713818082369,0.435588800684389,0.493032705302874,
0.550614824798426,0.60814515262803,0.667276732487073,0.728130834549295,0.790952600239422,
0.85714223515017,0.926423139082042,1.),.UNSPECIFIED.);
#1228=CARTESIAN_POINT('',(-6.4,-0.42729575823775,-0.435312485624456));
#1229=VERTEX_POINT('',#1228);
#1230=EDGE_CURVE('E1285',#1205,#1229,#1227,.T.);
#1231=ORIENTED_EDGE('',*,*,#1230,.T.);
#1232=DIRECTION('',(0.,1.,0.));
#1233=VECTOR('',#1232,1.);
#1234=CARTESIAN_POINT('',(-6.4,-0.42729575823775,-0.435312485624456));
#1235=LINE('',#1234,#1233);
#1236=CARTESIAN_POINT('',(-6.4,-0.426139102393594,-0.435312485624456));
#1237=VERTEX_POINT('',#1236);
#1238=EDGE_CURVE('E1394',#1229,#1237,#1235,.T.);
#1239=ORIENTED_EDGE('',*,*,#1238,.T.);
#1240=CARTESIAN_POINT('',(-6.4,-0.426139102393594,-0.435312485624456));
#1241=CARTESIAN_POINT('',(-6.4,-0.405302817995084,-0.435798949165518));
#1242=CARTESIAN_POINT('',(-6.4,-0.362890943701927,-0.436789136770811));
#1243=CARTESIAN_POINT('',(-6.4,-0.298519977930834,-0.443695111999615));
#1244=CARTESIAN_POINT('',(-6.4,-0.232427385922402,-0.454365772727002));
#1245=CARTESIAN_POINT('',(-6.4,-0.165204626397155,-0.470017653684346));
#1246=CARTESIAN_POINT('',(-6.4,-0.0975398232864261,-0.489102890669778));
#1247=CARTESIAN_POINT('',(-6.4,-0.0302120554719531,-0.511711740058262));
#1248=CARTESIAN_POINT('',(-6.4,0.036620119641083,-0.536851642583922));
#1249=CARTESIAN_POINT('',(-6.4,0.0801904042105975,-0.556523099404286));
#1250=CARTESIAN_POINT('',(-6.4,0.102067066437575,-0.566400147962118));
#1251=B_SPLINE_CURVE_WITH_KNOTS('',3,(#1240,#1241,#1242,#1243,#1244,#1245,#1246,#1247,#1248,
#1249,#1250),.UNSPECIFIED.,.F.,.F.,(4,1,1,1,1,1,1,1,4),(0.,0.114002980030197,0.232050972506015,
0.353906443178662,0.480147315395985,0.609491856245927,0.738474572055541,0.868687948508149,1.),.UNSPECIFIED.);
#1252=CARTESIAN_POINT('',(-6.4,0.102067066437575,-0.566400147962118));
#1253=VERTEX_POINT('',#1252);
#1254=EDGE_CURVE('E1387',#1237,#1253,#1251,.T.);
#1255=ORIENTED_EDGE('',*,*,#1254,.T.);
#1256=DIRECTION('',(0.,0.905627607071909,-0.424073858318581));
#1257=VECTOR('',#1256,1.);
#1258=CARTESIAN_POINT('',(-6.4,0.102067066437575,-0.566400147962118));
#1259=LINE('',#1258,#1257);
#1260=CARTESIAN_POINT('',(-6.4,0.922136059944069,-0.950409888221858));
#1261=VERTEX_POINT('',#1260);
#1262=EDGE_CURVE('E1393',#1253,#1261,#1259,.T.);
#1263=ORIENTED_EDGE('',*,*,#1262,.T.);
#1264=DIRECTION('',(0.,0.,-1.));
#1265=VECTOR('',#1264,1.);
#1266=CARTESIAN_POINT('',(-6.4,0.922136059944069,-0.950409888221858));
#1267=LINE('',#1266,#1265);
#1268=CARTESIAN_POINT('',(-6.4,0.922136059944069,-1.3536972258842));
#1269=VERTEX_POINT('',#1268);
#1270=EDGE_CURVE('E1400',#1261,#1269,#1267,.T.);
#1271=ORIENTED_EDGE('',*,*,#1270,.T.);
#1272=DIRECTION('',(0.,-0.900247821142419,0.435377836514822));
#1273=VECTOR('',#1272,1.);
#1274=CARTESIAN_POINT('',(-6.4,0.922136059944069,-1.3536972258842));
#1275=LINE('',#1274,#1273);
#1276=CARTESIAN_POINT('',(-6.4,0.151420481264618,-0.980963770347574));
#1277=VERTEX_POINT('',#1276);
#1278=EDGE_CURVE('E1402',#1269,#1277,#1275,.T.);
#1279=ORIENTED_EDGE('',*,*,#1278,.T.);
#1280=CARTESIAN_POINT('',(-6.4,0.027655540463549,-0.808526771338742));
#1281=CARTESIAN_POINT('',(-6.4,0.0380307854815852,-0.814367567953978));
#1282=CARTESIAN_POINT('',(-6.4,0.0583649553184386,-0.825814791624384));
#1283=CARTESIAN_POINT('',(-6.4,0.0846820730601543,-0.848364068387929));
#1284=CARTESIAN_POINT('',(-6.4,0.107536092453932,-0.873513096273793));
#1285=CARTESIAN_POINT('',(-6.4,0.125713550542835,-0.902598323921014));
#1286=CARTESIAN_POINT('',(-6.4,0.140094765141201,-0.934757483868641));
#1287=CARTESIAN_POINT('',(-6.4,0.149899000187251,-0.970253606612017));
#1288=CARTESIAN_POINT('',(-6.4,0.156331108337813,-1.00877990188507));
#1289=CARTESIAN_POINT('',(-6.4,0.156903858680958,-1.03558866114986));
#1290=CARTESIAN_POINT('',(-6.4,0.157200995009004,-1.04949673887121));
#1291=B_SPLINE_CURVE_WITH_KNOTS('',3,(#1280,#1281,#1282,#1283,#1284,#1285,#1286,#1287,#1288,
#1289,#1290),.UNSPECIFIED.,.F.,.F.,(4,1,1,1,1,1,1,1,4),(0.,0.123274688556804,0.24160281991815,
0.357777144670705,0.474683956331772,0.595870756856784,0.722082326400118,0.855819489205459,1.),.UNSPECIFIED.);
#1292=CARTESIAN_POINT('',(-6.4,0.157200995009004,-1.04949673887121));
#1293=VERTEX_POINT('',#1292);
#1294=EDGE_CURVE('E367',#1277,#1293,#1291,.T.);
#1295=ORIENTED_EDGE('',*,*,#1294,.T.);
#1296=CARTESIAN_POINT('',(-6.4,0.157200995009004,-1.04949673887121));
#1297=CARTESIAN_POINT('',(-6.4,0.156769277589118,-1.06853625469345));
#1298=CARTESIAN_POINT('',(-6.4,0.155929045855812,-1.10559198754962));
#1299=CARTESIAN_POINT('',(-6.4,0.149054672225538,-1.159511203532));
#1300=CARTESIAN_POINT('',(-6.4,0.136872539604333,-1.20990276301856));
#1301=CARTESIAN_POINT('',(-6.4,0.120880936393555,-1.25740101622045));
#1302=CARTESIAN_POINT('',(-6.4,0.0995562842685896,-1.30150728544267));
#1303=CARTESIAN_POINT('',(-6.4,0.0734630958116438,-1.34233095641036));
#1304=CARTESIAN_POINT('',(-6.4,0.0429140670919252,-1.37996717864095));
#1305=CARTESIAN_POINT('',(-6.4,0.00754236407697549,-1.41391992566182));
#1306=CARTESIAN_POINT('',(-6.4,-0.0317498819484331,-1.44450759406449));
#1307=CARTESIAN_POINT('',(-6.4,-0.075359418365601,-1.47071997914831));
#1308=CARTESIAN_POINT('',(-6.4,-0.122557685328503,-1.49324615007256));
#1309=CARTESIAN_POINT('',(-6.4,-0.173816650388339,-1.51119211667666));
#1310=CARTESIAN_POINT('',(-6.4,-0.22871985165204,-1.52557500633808));
#1311=CARTESIAN_POINT('',(-6.4,-0.287578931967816,-1.53528663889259));
#1312=CARTESIAN_POINT('',(-6.4,-0.350171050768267,-1.54170931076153));
#1313=CARTESIAN_POINT('',(-6.4,-0.393221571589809,-1.54230934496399));
#1314=CARTESIAN_POINT('',(-6.4,-0.415343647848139,-1.54261768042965));
#1315=B_SPLINE_CURVE_WITH_KNOTS('',3,(#1296,#1297,#1298,#1299,#1300,#1301,#1302,#1303,#1304,
#1305,#1306,#1307,#1308,#1309,#1310,#1311,#1312,#1313,#1314),.UNSPECIFIED.,.F.,.F.,(4,1,1,1,1,1,
1,1,1,1,1,1,1,1,1,1,4),(0.,0.0665766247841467,0.12957501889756,0.189644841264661,
0.247639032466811,0.304530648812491,0.36051483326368,0.416743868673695,0.473642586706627,
0.531631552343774,0.590524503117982,0.65124161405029,0.714220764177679,0.780176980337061,
0.849489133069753,0.922658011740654,1.),.UNSPECIFIED.);
#1316=CARTESIAN_POINT('',(-6.4,-0.415343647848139,-1.54261768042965));
#1317=VERTEX_POINT('',#1316);
#1318=EDGE_CURVE('E360',#1293,#1317,#1315,.T.);
#1319=ORIENTED_EDGE('',*,*,#1318,.T.);
#1320=DIRECTION('',(0.,-1.,0.));
#1321=VECTOR('',#1320,1.);
#1322=CARTESIAN_POINT('',(-6.4,-0.415343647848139,-1.54261768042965));
#1323=LINE('',#1322,#1321);
#1324=EDGE_CURVE('E366',#1317,#1203,#1323,.T.);
#1325=ORIENTED_EDGE('',*,*,#1324,.T.);
#1326=EDGE_LOOP('',(#1207,#1231,#1239,#1255,#1263,#1271,#1279,#1295,#1319,#1325));
#1327=FACE_BOUND('',#1326,.T.);
#1328=CARTESIAN_POINT('',(-6.4,-0.657084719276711,-0.988193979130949));
#1329=CARTESIAN_POINT('',(-6.4,-0.656505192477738,-1.00342452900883));
#1330=CARTESIAN_POINT('',(-6.4,-0.655408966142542,-1.03223446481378));
#1331=CARTESIAN_POINT('',(-6.4,-0.644883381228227,-1.07280878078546));
#1332=CARTESIAN_POINT('',(-6.4,-0.626891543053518,-1.10745157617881));
#1333=CARTESIAN_POINT('',(-6.4,-0.601919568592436,-1.1365052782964));
#1334=CARTESIAN_POINT('',(-6.4,-0.570019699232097,-1.15915178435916));
#1335=CARTESIAN_POINT('',(-6.4,-0.53163026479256,-1.17481836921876));
#1336=CARTESIAN_POINT('',(-6.4,-0.487413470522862,-1.18459989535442));
#1337=CARTESIAN_POINT('',(-6.4,-0.455882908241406,-1.18550474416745));
#1338=CARTESIAN_POINT('',(-6.4,-0.43924786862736,-1.1859821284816));
#1339=B_SPLINE_CURVE_WITH_KNOTS('',3,(#1328,#1329,#1330,#1331,#1332,#1333,#1334,#1335,#1336,
#1337,#1338),.UNSPECIFIED.,.F.,.F.,(4,1,1,1,1,1,1,1,4),(0.,0.136105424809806,0.257455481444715,
0.371657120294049,0.482556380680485,0.597133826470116,0.718249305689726,0.851352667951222,1.),.UNSPECIFIED.);
#1340=CARTESIAN_POINT('',(-6.4,-0.657084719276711,-0.988193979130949));
#1341=VERTEX_POINT('',#1340);
#1342=CARTESIAN_POINT('',(-6.4,-0.43924786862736,-1.1859821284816));
#1343=VERTEX_POINT('',#1342);
#1344=EDGE_CURVE('E299',#1341,#1343,#1339,.T.);
#1345=ORIENTED_EDGE('',*,*,#1344,.T.);
#1346=DIRECTION('',(0.,1.,0.));
#1347=VECTOR('',#1346,1.);
#1348=CARTESIAN_POINT('',(-6.4,-0.43924786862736,-1.1859821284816));
#1349=LINE('',#1348,#1347);
#1350=CARTESIAN_POINT('',(-6.4,-0.438091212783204,-1.1859821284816));
#1351=VERTEX_POINT('',#1350);
#1352=EDGE_CURVE('E320',#1343,#1351,#1349,.T.);
#1353=ORIENTED_EDGE('',*,*,#1352,.T.);
#1354=CARTESIAN_POINT('',(-6.4,-0.438091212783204,-1.1859821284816));
#1355=CARTESIAN_POINT('',(-6.4,-0.419148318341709,-1.18550701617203));
#1356=CARTESIAN_POINT('',(-6.4,-0.383297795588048,-1.18460783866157));
#1357=CARTESIAN_POINT('',(-6.4,-0.332999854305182,-1.17486054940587));
#1358=CARTESIAN_POINT('',(-6.4,-0.289209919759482,-1.1593807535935));
#1359=CARTESIAN_POINT('',(-6.4,-0.252742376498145,-1.13669042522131));
#1360=CARTESIAN_POINT('',(-6.4,-0.223128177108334,-1.10828502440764));
#1361=CARTESIAN_POINT('',(-6.4,-0.202904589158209,-1.07304263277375));
#1362=CARTESIAN_POINT('',(-6.4,-0.189871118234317,-1.03253366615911));
#1363=CARTESIAN_POINT('',(-6.4,-0.18881081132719,-1.00346924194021));
#1364=CARTESIAN_POINT('',(-6.4,-0.188253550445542,-0.988193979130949));
#1365=B_SPLINE_CURVE_WITH_KNOTS('',3,(#1354,#1355,#1356,#1357,#1358,#1359,#1360,#1361,#1362,
#1363,#1364),.UNSPECIFIED.,.F.,.F.,(4,1,1,1,1,1,1,1,4),(0.,0.15694181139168,0.297021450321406,
0.423167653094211,0.540011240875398,0.650824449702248,0.759791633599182,0.873754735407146,1.),.UNSPECIFIED.);
#1366=CARTESIAN_POINT('',(-6.4,-0.188253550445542,-0.988193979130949));
#1367=VERTEX_POINT('',#1366);
#1368=EDGE_CURVE('E322',#1351,#1367,#1365,.T.);
#1369=ORIENTED_EDGE('',*,*,#1368,.T.);
#1370=CARTESIAN_POINT('',(-6.4,-0.188253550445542,-0.988193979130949));
#1371=CARTESIAN_POINT('',(-6.4,-0.189064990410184,-0.973339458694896));
#1372=CARTESIAN_POINT('',(-6.4,-0.190618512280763,-0.944900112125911));
#1373=CARTESIAN_POINT('',(-6.4,-0.202579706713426,-0.904501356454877));
#1374=CARTESIAN_POINT('',(-6.4,-0.224319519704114,-0.870237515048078));
#1375=CARTESIAN_POINT('',(-6.4,-0.253313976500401,-0.84100908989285));
#1376=CARTESIAN_POINT('',(-6.4,-0.290438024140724,-0.818789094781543));
#1377=CARTESIAN_POINT('',(-6.4,-0.334032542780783,-0.802522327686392));
#1378=CARTESIAN_POINT('',(-6.4,-0.384478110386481,-0.792987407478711));
#1379=CARTESIAN_POINT('',(-6.4,-0.420313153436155,-0.792055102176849));
#1380=CARTESIAN_POINT('',(-6.4,-0.43924786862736,-0.791562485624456));
#1381=B_SPLINE_CURVE_WITH_KNOTS('',3,(#1370,#1371,#1372,#1373,#1374,#1375,#1376,#1377,#1378,
#1379,#1380),.UNSPECIFIED.,.F.,.F.,(4,1,1,1,1,1,1,1,4),(0.,0.123427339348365,0.236304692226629,
0.345705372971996,0.457515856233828,0.575525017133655,0.702323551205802,0.842712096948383,1.),.UNSPECIFIED.);
#1382=CARTESIAN_POINT('',(-6.40000000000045,-0.43924786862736,-0.791562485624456));
#1383=VERTEX_POINT('',#1382);
#1384=EDGE_CURVE('E1227',#1367,#1383,#1381,.T.);
#1385=ORIENTED_EDGE('',*,*,#1384,.T.);
#1386=DIRECTION('',(0.,-1.,0.));
#1387=VECTOR('',#1386,1.);
#1388=CARTESIAN_POINT('',(-6.4,-0.43924786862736,-0.791562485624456));
#1389=LINE('',#1388,#1387);
#1390=CARTESIAN_POINT('',(-6.4,-0.440790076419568,-0.791562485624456));
#1391=VERTEX_POINT('',#1390);
#1392=EDGE_CURVE('E303',#1383,#1391,#1389,.T.);
#1393=ORIENTED_EDGE('',*,*,#1392,.T.);
#1394=CARTESIAN_POINT('',(-6.4,-0.440790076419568,-0.791562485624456));
#1395=CARTESIAN_POINT('',(-6.4,-0.457288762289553,-0.792065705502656));
#1396=CARTESIAN_POINT('',(-6.4,-0.488675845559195,-0.793023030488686));
#1397=CARTESIAN_POINT('',(-6.4,-0.532790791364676,-0.802538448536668));
#1398=CARTESIAN_POINT('',(-6.4,-0.570725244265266,-0.818866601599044));
#1399=CARTESIAN_POINT('',(-6.4,-0.602476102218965,-0.841535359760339));
#1400=CARTESIAN_POINT('',(-6.4,-0.627116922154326,-0.870668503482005));
#1401=CARTESIAN_POINT('',(-6.4,-0.644821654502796,-0.905192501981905));
#1402=CARTESIAN_POINT('',(-6.4,-0.655367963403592,-0.94504504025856));
#1403=CARTESIAN_POINT('',(-6.4,-0.656494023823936,-0.973347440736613));
#1404=CARTESIAN_POINT('',(-6.4,-0.657084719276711,-0.988193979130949));
#1405=B_SPLINE_CURVE_WITH_KNOTS('',3,(#1394,#1395,#1396,#1397,#1398,#1399,#1400,#1401,#1402,
#1403,#1404),.UNSPECIFIED.,.F.,.F.,(4,1,1,1,1,1,1,1,4),(0.,0.148675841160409,0.282840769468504,
0.404315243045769,0.518865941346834,0.631529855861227,0.745078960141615,0.866276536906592,1.),.UNSPECIFIED.);
#1406=EDGE_CURVE('E295',#1391,#1341,#1405,.T.);
#1407=ORIENTED_EDGE('',*,*,#1406,.T.);
#1408=EDGE_LOOP('',(#1345,#1353,#1369,#1385,#1393,#1407));
#1409=FACE_BOUND('',#1408,.T.);
#1410=ADVANCED_FACE('F297',(#1327,#1409),#1181,.F.);
#1411=DIRECTION('',(-1.,0.,0.));
#1412=VECTOR('',#1411,1.);
#1413=SURFACE_OF_LINEAR_EXTRUSION('',#1201,#1412);
#1414=ORIENTED_EDGE('',*,*,#72,.T.);
#1415=DIRECTION('',(-1.,0.,0.));
#1416=VECTOR('',#1415,1.);
#1417=CARTESIAN_POINT('',(-6.4,-1.00253926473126,-0.988193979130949));
#1418=LINE('',#1417,#1416);
#1419=EDGE_CURVE('E377',#1205,#45,#1418,.T.);
#1420=ORIENTED_EDGE('',*,*,#1419,.F.);
#1421=ORIENTED_EDGE('',*,*,#1206,.F.);
#1422=DIRECTION('',(-1.,0.,0.));
#1423=VECTOR('',#1422,1.);
#1424=CARTESIAN_POINT('',(-6.4,-0.416885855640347,-1.54261768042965));
#1425=LINE('',#1424,#1423);
#1426=EDGE_CURVE('E432',#1203,#71,#1425,.T.);
#1427=ORIENTED_EDGE('',*,*,#1426,.T.);
#1428=EDGE_LOOP('',(#1414,#1420,#1421,#1427));
#1429=FACE_BOUND('',#1428,.T.);
#1430=ADVANCED_FACE('F345',(#1429),#1413,.F.);
#1431=CARTESIAN_POINT('',(-6.4,-0.415343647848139,-1.54261768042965));
#1432=DIRECTION('',(0.,0.,-1.));
#1433=DIRECTION('',(-1.,0.,0.));
#1434=AXIS2_PLACEMENT_3D('',#1431,#1432,#1433);
#1435=PLANE('',#1434);
#1436=ORIENTED_EDGE('',*,*,#80,.T.);
#1437=ORIENTED_EDGE('',*,*,#1426,.F.);
#1438=ORIENTED_EDGE('',*,*,#1324,.F.);
#1439=DIRECTION('',(-1.,0.,0.));
#1440=VECTOR('',#1439,1.);
#1441=CARTESIAN_POINT('',(-6.4,-0.415343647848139,-1.54261768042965));
#1442=LINE('',#1441,#1440);
#1443=EDGE_CURVE('E435',#1317,#79,#1442,.T.);
#1444=ORIENTED_EDGE('',*,*,#1443,.T.);
#1445=EDGE_LOOP('',(#1436,#1437,#1438,#1444));
#1446=FACE_BOUND('',#1445,.T.);
#1447=ADVANCED_FACE('F348',(#1446),#1435,.F.);
#1448=DIRECTION('',(-1.,0.,0.));
#1449=VECTOR('',#1448,1.);
#1450=SURFACE_OF_LINEAR_EXTRUSION('',#1315,#1449);
#1451=ORIENTED_EDGE('',*,*,#104,.T.);
#1452=ORIENTED_EDGE('',*,*,#1443,.F.);
#1453=ORIENTED_EDGE('',*,*,#1318,.F.);
#1454=DIRECTION('',(-1.,0.,0.));
#1455=VECTOR('',#1454,1.);
#1456=CARTESIAN_POINT('',(-6.4,0.157200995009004,-1.04949673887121));
#1457=LINE('',#1456,#1455);
#1458=EDGE_CURVE('E437',#1293,#103,#1457,.T.);
#1459=ORIENTED_EDGE('',*,*,#1458,.T.);
#1460=EDGE_LOOP('',(#1451,#1452,#1453,#1459));
#1461=FACE_BOUND('',#1460,.T.);
#1462=ADVANCED_FACE('F351',(#1461),#1450,.F.);
#1463=DIRECTION('',(-1.,0.,0.));
#1464=VECTOR('',#1463,1.);
#1465=SURFACE_OF_LINEAR_EXTRUSION('',#1291,#1464);
#1466=ORIENTED_EDGE('',*,*,#120,.T.);
#1467=ORIENTED_EDGE('',*,*,#1458,.F.);
#1468=ORIENTED_EDGE('',*,*,#1294,.F.);
#1469=DIRECTION('',(-1.,0.,0.));
#1470=VECTOR('',#1469,1.);
#1471=CARTESIAN_POINT('',(-6.4,0.151420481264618,-0.980963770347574));
#1472=LINE('',#1471,#1470);
#1473=EDGE_CURVE('E439',#1277,#119,#1472,.T.);
#1474=ORIENTED_EDGE('',*,*,#1473,.T.);
#1475=EDGE_LOOP('',(#1466,#1467,#1468,#1474));
#1476=FACE_BOUND('',#1475,.T.);
#1477=ADVANCED_FACE('F356',(#1476),#1465,.F.);
#1478=CARTESIAN_POINT('',(-6.4,0.922136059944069,-1.3536972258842));
#1479=DIRECTION('',(0.,-0.435377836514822,-0.900247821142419));
#1480=DIRECTION('',(0.,0.900247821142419,-0.435377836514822));
#1481=AXIS2_PLACEMENT_3D('',#1478,#1479,#1480);
#1482=PLANE('',#1481);
#1483=ORIENTED_EDGE('',*,*,#128,.T.);
#1484=ORIENTED_EDGE('',*,*,#1473,.F.);
#1485=ORIENTED_EDGE('',*,*,#1278,.F.);
#1486=DIRECTION('',(-1.,0.,0.));
#1487=VECTOR('',#1486,1.);
#1488=CARTESIAN_POINT('',(-6.4,0.922136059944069,-1.3536972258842));
#1489=LINE('',#1488,#1487);
#1490=EDGE_CURVE('E441',#1269,#127,#1489,.T.);
#1491=ORIENTED_EDGE('',*,*,#1490,.T.);
#1492=EDGE_LOOP('',(#1483,#1484,#1485,#1491));
#1493=FACE_BOUND('',#1492,.T.);
#1494=ADVANCED_FACE('F901',(#1493),#1482,.F.);
#1495=CARTESIAN_POINT('',(-6.4,0.922136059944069,-0.950409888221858));
#1496=DIRECTION('',(0.,1.,0.));
#1497=DIRECTION('',(0.,0.,1.));
#1498=AXIS2_PLACEMENT_3D('',#1495,#1496,#1497);
#1499=PLANE('',#1498);
#1500=ORIENTED_EDGE('',*,*,#136,.T.);
#1501=ORIENTED_EDGE('',*,*,#1490,.F.);
#1502=ORIENTED_EDGE('',*,*,#1270,.F.);
#1503=DIRECTION('',(-1.,0.,0.));
#1504=VECTOR('',#1503,1.);
#1505=CARTESIAN_POINT('',(-6.4,0.922136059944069,-0.950409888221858));
#1506=LINE('',#1505,#1504);
#1507=EDGE_CURVE('E443',#1261,#135,#1506,.T.);
#1508=ORIENTED_EDGE('',*,*,#1507,.T.);
#1509=EDGE_LOOP('',(#1500,#1501,#1502,#1508));
#1510=FACE_BOUND('',#1509,.T.);
#1511=ADVANCED_FACE('F908',(#1510),#1499,.F.);
#1512=CARTESIAN_POINT('',(-6.4,0.102067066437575,-0.566400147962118));
#1513=DIRECTION('',(0.,0.424073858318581,0.905627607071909));
#1514=DIRECTION('',(0.,-0.905627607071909,0.424073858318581));
#1515=AXIS2_PLACEMENT_3D('',#1512,#1513,#1514);
#1516=PLANE('',#1515);
#1517=ORIENTED_EDGE('',*,*,#144,.T.);
#1518=ORIENTED_EDGE('',*,*,#1507,.F.);
#1519=ORIENTED_EDGE('',*,*,#1262,.F.);
#1520=DIRECTION('',(-1.,0.,0.));
#1521=VECTOR('',#1520,1.);
#1522=CARTESIAN_POINT('',(-6.4,0.102067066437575,-0.566400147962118));
#1523=LINE('',#1522,#1521);
#1524=EDGE_CURVE('E445',#1253,#143,#1523,.T.);
#1525=ORIENTED_EDGE('',*,*,#1524,.T.);
#1526=EDGE_LOOP('',(#1517,#1518,#1519,#1525));
#1527=FACE_BOUND('',#1526,.T.);
#1528=ADVANCED_FACE('F915',(#1527),#1516,.F.);
#1529=DIRECTION('',(-1.,0.,0.));
#1530=VECTOR('',#1529,1.);
#1531=SURFACE_OF_LINEAR_EXTRUSION('',#1251,#1530);
#1532=ORIENTED_EDGE('',*,*,#160,.T.);
#1533=ORIENTED_EDGE('',*,*,#1524,.F.);
#1534=ORIENTED_EDGE('',*,*,#1254,.F.);
#1535=DIRECTION('',(-1.,0.,0.));
#1536=VECTOR('',#1535,1.);
#1537=CARTESIAN_POINT('',(-6.4,-0.426139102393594,-0.435312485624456));
#1538=LINE('',#1537,#1536);
#1539=EDGE_CURVE('E447',#1237,#159,#1538,.T.);
#1540=ORIENTED_EDGE('',*,*,#1539,.T.);
#1541=EDGE_LOOP('',(#1532,#1533,#1534,#1540));
#1542=FACE_BOUND('',#1541,.T.);
#1543=ADVANCED_FACE('F923',(#1542),#1531,.F.);
#1544=CARTESIAN_POINT('',(-6.4,-0.42729575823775,-0.435312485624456));
#1545=DIRECTION('',(0.,0.,1.));
#1546=DIRECTION('',(1.,0.,0.));
#1547=AXIS2_PLACEMENT_3D('',#1544,#1545,#1546);
#1548=PLANE('',#1547);
#1549=ORIENTED_EDGE('',*,*,#166,.T.);
#1550=ORIENTED_EDGE('',*,*,#1539,.F.);
#1551=ORIENTED_EDGE('',*,*,#1238,.F.);
#1552=DIRECTION('',(-1.,0.,0.));
#1553=VECTOR('',#1552,1.);
#1554=CARTESIAN_POINT('',(-6.4,-0.42729575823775,-0.435312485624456));
#1555=LINE('',#1554,#1553);
#1556=EDGE_CURVE('E449',#1229,#47,#1555,.T.);
#1557=ORIENTED_EDGE('',*,*,#1556,.T.);
#1558=EDGE_LOOP('',(#1549,#1550,#1551,#1557));
#1559=FACE_BOUND('',#1558,.T.);
#1560=ADVANCED_FACE('F931',(#1559),#1548,.F.);
#1561=DIRECTION('',(-1.,0.,0.));
#1562=VECTOR('',#1561,1.);
#1563=SURFACE_OF_LINEAR_EXTRUSION('',#1227,#1562);
#1564=ORIENTED_EDGE('',*,*,#48,.T.);
#1565=ORIENTED_EDGE('',*,*,#1556,.F.);
#1566=ORIENTED_EDGE('',*,*,#1230,.F.);
#1567=ORIENTED_EDGE('',*,*,#1419,.T.);
#1568=EDGE_LOOP('',(#1564,#1565,#1566,#1567));
#1569=FACE_BOUND('',#1568,.T.);
#1570=ADVANCED_FACE('F342',(#1569),#1563,.F.);
#1571=DIRECTION('',(-1.,0.,0.));
#1572=VECTOR('',#1571,1.);
#1573=SURFACE_OF_LINEAR_EXTRUSION('',#1405,#1572);
#1574=CARTESIAN_POINT('',(-7.,-0.440790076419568,-0.791562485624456));
#1575=CARTESIAN_POINT('',(-7.,-0.457288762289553,-0.792065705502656));
#1576=CARTESIAN_POINT('',(-7.,-0.488675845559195,-0.793023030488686));
#1577=CARTESIAN_POINT('',(-7.,-0.532790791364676,-0.802538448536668));
#1578=CARTESIAN_POINT('',(-7.,-0.570725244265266,-0.818866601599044));
#1579=CARTESIAN_POINT('',(-7.,-0.602476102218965,-0.841535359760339));
#1580=CARTESIAN_POINT('',(-7.,-0.627116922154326,-0.870668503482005));
#1581=CARTESIAN_POINT('',(-7.,-0.644821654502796,-0.905192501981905));
#1582=CARTESIAN_POINT('',(-7.,-0.655367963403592,-0.94504504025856));
#1583=CARTESIAN_POINT('',(-7.,-0.656494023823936,-0.973347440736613));
#1584=CARTESIAN_POINT('',(-7.,-0.657084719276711,-0.988193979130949));
#1585=B_SPLINE_CURVE_WITH_KNOTS('',3,(#1574,#1575,#1576,#1577,#1578,#1579,#1580,#1581,#1582,
#1583,#1584),.UNSPECIFIED.,.F.,.F.,(4,1,1,1,1,1,1,1,4),(0.,0.148675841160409,0.282840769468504,
0.404315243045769,0.518865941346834,0.631529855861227,0.745078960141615,0.866276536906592,1.),.UNSPECIFIED.);
#1586=CARTESIAN_POINT('',(-7.00000000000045,-0.440790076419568,-0.791562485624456));
#1587=VERTEX_POINT('',#1586);
#1588=CARTESIAN_POINT('',(-7.,-0.657084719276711,-0.988193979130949));
#1589=VERTEX_POINT('',#1588);
#1590=EDGE_CURVE('E312',#1587,#1589,#1585,.T.);
#1591=ORIENTED_EDGE('',*,*,#1590,.T.);
#1592=DIRECTION('',(-1.,0.,0.));
#1593=VECTOR('',#1592,1.);
#1594=CARTESIAN_POINT('',(-6.4,-0.657084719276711,-0.988193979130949));
#1595=LINE('',#1594,#1593);
#1596=EDGE_CURVE('E309',#1341,#1589,#1595,.T.);
#1597=ORIENTED_EDGE('',*,*,#1596,.F.);
#1598=ORIENTED_EDGE('',*,*,#1406,.F.);
#1599=DIRECTION('',(-1.,0.,0.));
#1600=VECTOR('',#1599,1.);
#1601=CARTESIAN_POINT('',(-6.4,-0.440790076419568,-0.791562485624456));
#1602=LINE('',#1601,#1600);
#1603=EDGE_CURVE('E1239',#1391,#1587,#1602,.T.);
#1604=ORIENTED_EDGE('',*,*,#1603,.T.);
#1605=EDGE_LOOP('',(#1591,#1597,#1598,#1604));
#1606=FACE_BOUND('',#1605,.T.);
#1607=ADVANCED_FACE('F310',(#1606),#1573,.F.);
#1608=DIRECTION('',(-1.,0.,0.));
#1609=VECTOR('',#1608,1.);
#1610=SURFACE_OF_LINEAR_EXTRUSION('',#1339,#1609);
#1611=CARTESIAN_POINT('',(-7.,-0.657084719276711,-0.988193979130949));
#1612=CARTESIAN_POINT('',(-7.,-0.656505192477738,-1.00342452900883));
#1613=CARTESIAN_POINT('',(-7.,-0.655408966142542,-1.03223446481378));
#1614=CARTESIAN_POINT('',(-7.,-0.644883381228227,-1.07280878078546));
#1615=CARTESIAN_POINT('',(-7.,-0.626891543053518,-1.10745157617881));
#1616=CARTESIAN_POINT('',(-7.,-0.601919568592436,-1.1365052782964));
#1617=CARTESIAN_POINT('',(-7.,-0.570019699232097,-1.15915178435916));
#1618=CARTESIAN_POINT('',(-7.,-0.53163026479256,-1.17481836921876));
#1619=CARTESIAN_POINT('',(-7.,-0.487413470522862,-1.18459989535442));
#1620=CARTESIAN_POINT('',(-7.,-0.455882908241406,-1.18550474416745));
#1621=CARTESIAN_POINT('',(-7.,-0.43924786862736,-1.1859821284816));
#1622=B_SPLINE_CURVE_WITH_KNOTS('',3,(#1611,#1612,#1613,#1614,#1615,#1616,#1617,#1618,#1619,
#1620,#1621),.UNSPECIFIED.,.F.,.F.,(4,1,1,1,1,1,1,1,4),(0.,0.136105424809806,0.257455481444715,
0.371657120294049,0.482556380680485,0.597133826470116,0.718249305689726,0.851352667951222,1.),.UNSPECIFIED.);
#1623=CARTESIAN_POINT('',(-7.,-0.43924786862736,-1.1859821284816));
#1624=VERTEX_POINT('',#1623);
#1625=EDGE_CURVE('E1243',#1589,#1624,#1622,.T.);
#1626=ORIENTED_EDGE('',*,*,#1625,.T.);
#1627=DIRECTION('',(-1.,0.,0.));
#1628=VECTOR('',#1627,1.);
#1629=CARTESIAN_POINT('',(-6.4,-0.43924786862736,-1.1859821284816));
#1630=LINE('',#1629,#1628);
#1631=EDGE_CURVE('E316',#1343,#1624,#1630,.T.);
#1632=ORIENTED_EDGE('',*,*,#1631,.F.);
#1633=ORIENTED_EDGE('',*,*,#1344,.F.);
#1634=ORIENTED_EDGE('',*,*,#1596,.T.);
#1635=EDGE_LOOP('',(#1626,#1632,#1633,#1634));
#1636=FACE_BOUND('',#1635,.T.);
#1637=ADVANCED_FACE('F318',(#1636),#1610,.F.);
#1638=CARTESIAN_POINT('',(-6.4,-0.43924786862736,-1.1859821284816));
#1639=DIRECTION('',(0.,0.,1.));
#1640=DIRECTION('',(1.,0.,0.));
#1641=AXIS2_PLACEMENT_3D('',#1638,#1639,#1640);
#1642=PLANE('',#1641);
#1643=DIRECTION('',(0.,1.,0.));
#1644=VECTOR('',#1643,1.);
#1645=CARTESIAN_POINT('',(-7.,-0.43924786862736,-1.1859821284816));
#1646=LINE('',#1645,#1644);
#1647=CARTESIAN_POINT('',(-7.,-0.438091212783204,-1.1859821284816));
#1648=VERTEX_POINT('',#1647);
#1649=EDGE_CURVE('E1250',#1624,#1648,#1646,.T.);
#1650=ORIENTED_EDGE('',*,*,#1649,.T.);
#1651=DIRECTION('',(-1.,0.,0.));
#1652=VECTOR('',#1651,1.);
#1653=CARTESIAN_POINT('',(-6.4,-0.438091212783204,-1.1859821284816));
#1654=LINE('',#1653,#1652);
#1655=EDGE_CURVE('E1277',#1351,#1648,#1654,.T.);
#1656=ORIENTED_EDGE('',*,*,#1655,.F.);
#1657=ORIENTED_EDGE('',*,*,#1352,.F.);
#1658=ORIENTED_EDGE('',*,*,#1631,.T.);
#1659=EDGE_LOOP('',(#1650,#1656,#1657,#1658));
#1660=FACE_BOUND('',#1659,.T.);
#1661=ADVANCED_FACE('F338',(#1660),#1642,.F.);
#1662=DIRECTION('',(-1.,0.,0.));
#1663=VECTOR('',#1662,1.);
#1664=SURFACE_OF_LINEAR_EXTRUSION('',#1365,#1663);
#1665=CARTESIAN_POINT('',(-7.,-0.438091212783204,-1.1859821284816));
#1666=CARTESIAN_POINT('',(-7.,-0.419148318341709,-1.18550701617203));
#1667=CARTESIAN_POINT('',(-7.,-0.383297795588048,-1.18460783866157));
#1668=CARTESIAN_POINT('',(-7.,-0.332999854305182,-1.17486054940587));
#1669=CARTESIAN_POINT('',(-7.,-0.289209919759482,-1.1593807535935));
#1670=CARTESIAN_POINT('',(-7.,-0.252742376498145,-1.13669042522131));
#1671=CARTESIAN_POINT('',(-7.,-0.223128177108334,-1.10828502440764));
#1672=CARTESIAN_POINT('',(-7.,-0.202904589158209,-1.07304263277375));
#1673=CARTESIAN_POINT('',(-7.,-0.189871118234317,-1.03253366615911));
#1674=CARTESIAN_POINT('',(-7.,-0.18881081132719,-1.00346924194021));
#1675=CARTESIAN_POINT('',(-7.,-0.188253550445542,-0.988193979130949));
#1676=B_SPLINE_CURVE_WITH_KNOTS('',3,(#1665,#1666,#1667,#1668,#1669,#1670,#1671,#1672,#1673,
#1674,#1675),.UNSPECIFIED.,.F.,.F.,(4,1,1,1,1,1,1,1,4),(0.,0.15694181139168,0.297021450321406,
0.423167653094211,0.540011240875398,0.650824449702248,0.759791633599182,0.873754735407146,1.),.UNSPECIFIED.);
#1677=CARTESIAN_POINT('',(-7.,-0.188253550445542,-0.988193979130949));
#1678=VERTEX_POINT('',#1677);
#1679=EDGE_CURVE('E1256',#1648,#1678,#1676,.T.);
#1680=ORIENTED_EDGE('',*,*,#1679,.T.);
#1681=DIRECTION('',(-1.,0.,0.));
#1682=VECTOR('',#1681,1.);
#1683=CARTESIAN_POINT('',(-6.4,-0.188253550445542,-0.988193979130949));
#1684=LINE('',#1683,#1682);
#1685=EDGE_CURVE('E1275',#1367,#1678,#1684,.T.);
#1686=ORIENTED_EDGE('',*,*,#1685,.F.);
#1687=ORIENTED_EDGE('',*,*,#1368,.F.);
#1688=ORIENTED_EDGE('',*,*,#1655,.T.);
#1689=EDGE_LOOP('',(#1680,#1686,#1687,#1688));
#1690=FACE_BOUND('',#1689,.T.);
#1691=ADVANCED_FACE('F961',(#1690),#1664,.F.);
#1692=DIRECTION('',(-1.,0.,0.));
#1693=VECTOR('',#1692,1.);
#1694=SURFACE_OF_LINEAR_EXTRUSION('',#1381,#1693);
#1695=CARTESIAN_POINT('',(-7.,-0.188253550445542,-0.988193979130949));
#1696=CARTESIAN_POINT('',(-7.,-0.189064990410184,-0.973339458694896));
#1697=CARTESIAN_POINT('',(-7.,-0.190618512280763,-0.944900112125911));
#1698=CARTESIAN_POINT('',(-7.,-0.202579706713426,-0.904501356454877));
#1699=CARTESIAN_POINT('',(-7.,-0.224319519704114,-0.870237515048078));
#1700=CARTESIAN_POINT('',(-7.,-0.253313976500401,-0.84100908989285));
#1701=CARTESIAN_POINT('',(-7.,-0.290438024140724,-0.818789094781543));
#1702=CARTESIAN_POINT('',(-7.,-0.334032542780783,-0.802522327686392));
#1703=CARTESIAN_POINT('',(-7.,-0.384478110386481,-0.792987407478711));
#1704=CARTESIAN_POINT('',(-7.,-0.420313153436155,-0.792055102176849));
#1705=CARTESIAN_POINT('',(-7.,-0.43924786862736,-0.791562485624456));
#1706=B_SPLINE_CURVE_WITH_KNOTS('',3,(#1695,#1696,#1697,#1698,#1699,#1700,#1701,#1702,#1703,
#1704,#1705),.UNSPECIFIED.,.F.,.F.,(4,1,1,1,1,1,1,1,4),(0.,0.123427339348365,0.236304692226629,
0.345705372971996,0.457515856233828,0.575525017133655,0.702323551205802,0.842712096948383,1.),.UNSPECIFIED.);
#1707=CARTESIAN_POINT('',(-7.,-0.43924786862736,-0.791562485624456));
#1708=VERTEX_POINT('',#1707);
#1709=EDGE_CURVE('E62',#1678,#1708,#1706,.T.);
#1710=ORIENTED_EDGE('',*,*,#1709,.T.);
#1711=DIRECTION('',(-1.,0.,0.));
#1712=VECTOR('',#1711,1.);
#1713=CARTESIAN_POINT('',(-6.4,-0.43924786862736,-0.791562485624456));
#1714=LINE('',#1713,#1712);
#1715=EDGE_CURVE('E1273',#1383,#1708,#1714,.T.);
#1716=ORIENTED_EDGE('',*,*,#1715,.F.);
#1717=ORIENTED_EDGE('',*,*,#1384,.F.);
#1718=ORIENTED_EDGE('',*,*,#1685,.T.);
#1719=EDGE_LOOP('',(#1710,#1716,#1717,#1718));
#1720=FACE_BOUND('',#1719,.T.);
#1721=ADVANCED_FACE('F544',(#1720),#1694,.F.);
#1722=CARTESIAN_POINT('',(-6.4,-0.43924786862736,-0.791562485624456));
#1723=DIRECTION('',(0.,0.,-1.));
#1724=DIRECTION('',(-1.,0.,0.));
#1725=AXIS2_PLACEMENT_3D('',#1722,#1723,#1724);
#1726=PLANE('',#1725);
#1727=DIRECTION('',(0.,-1.,0.));
#1728=VECTOR('',#1727,1.);
#1729=CARTESIAN_POINT('',(-7.,-0.43924786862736,-0.791562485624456));
#1730=LINE('',#1729,#1728);
#1731=EDGE_CURVE('E306',#1708,#1587,#1730,.T.);
#1732=ORIENTED_EDGE('',*,*,#1731,.T.);
#1733=ORIENTED_EDGE('',*,*,#1603,.F.);
#1734=ORIENTED_EDGE('',*,*,#1392,.F.);
#1735=ORIENTED_EDGE('',*,*,#1715,.T.);
#1736=EDGE_LOOP('',(#1732,#1733,#1734,#1735));
#1737=FACE_BOUND('',#1736,.T.);
#1738=ADVANCED_FACE('F539',(#1737),#1726,.F.);
#1739=ORIENTED_EDGE('',*,*,#1625,.F.);
#1740=ORIENTED_EDGE('',*,*,#1590,.F.);
#1741=ORIENTED_EDGE('',*,*,#1731,.F.);
#1742=ORIENTED_EDGE('',*,*,#1709,.F.);
#1743=ORIENTED_EDGE('',*,*,#1679,.F.);
#1744=ORIENTED_EDGE('',*,*,#1649,.F.);
#1745=EDGE_LOOP('',(#1739,#1740,#1741,#1742,#1743,#1744));
#1746=FACE_BOUND('',#1745,.T.);
#1747=ADVANCED_FACE('F537',(#1746),#23,.F.);
#1748=CLOSED_SHELL('',(#440,#460,#480,#497,#529,#553,#577,#601,#625,#649,#666,#681,#693,#724,
#748,#772,#796,#826,#850,#888,#926,#950,#974,#998,#1028,#1058,#1082,#1110,#1134,#1151,#1176,
#1410,#1430,#1447,#1462,#1477,#1494,#1511,#1528,#1543,#1560,#1570,#1607,#1637,#1661,#1691,#1721,
#1738,#1747));
#1749=MANIFOLD_SOLID_BREP('B2',#1748);
#1750=ADVANCED_BREP_SHAPE_REPRESENTATION('',(#18,#1749),#14);
#1751=SHAPE_DEFINITION_REPRESENTATION(#9,#1750);
ENDSEC;
END-ISO-10303-21;
